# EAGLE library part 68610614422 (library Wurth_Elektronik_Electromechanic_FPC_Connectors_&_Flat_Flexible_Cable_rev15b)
WR-FPC 1.00mm SMT ZIF Horizontal Bottom Contact, 6 Pins=>Code : Con_FPC_ZIF_1.00_68610614422 Details see: http://katalog.we-online.de/en/em/686_1xx_144_22 Created 2014-07-09, Karrer Zheng 2014 (C) Würth Elektronik

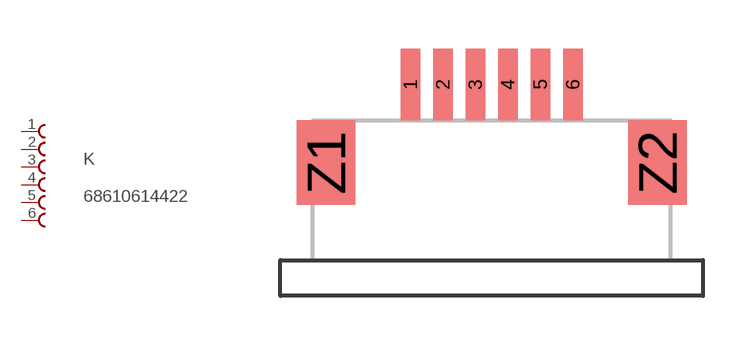
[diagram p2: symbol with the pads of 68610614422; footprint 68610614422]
Designator prefix K

## 68610614422  [68610614422]
1  1  pas
2  2  pas
3  3  pas
4  4  pas
5  5  pas
6  6  pas

## Footprint 68610614422 (pad centres in mm)
WR-FPC 1.00mm SMT ZIF Horizontal Bottom Contact, 6 Pins
smd 0.6 x 2.2: 1 -2.5,1.1; 2 -1.5,1.1; 3 -0.5,1.1; 4 0.5,1.1; 5 1.5,1.1; 6 2.5,1.1
smd 1.8 x 2.6: Z1 -5.1,-1.3; Z2 5.1,-1.3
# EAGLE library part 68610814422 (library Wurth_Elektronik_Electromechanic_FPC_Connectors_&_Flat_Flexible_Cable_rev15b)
WR-FPC 1.00mm SMT ZIF Horizontal Bottom Contact, 8 Pins=>Code : Con_FPC_ZIF_1.00_68610814422 Details see: http://katalog.we-online.de/en/em/686_1xx_144_22 Created 2014-07-09, Karrer Zheng 2014 (C) Würth Elektronik

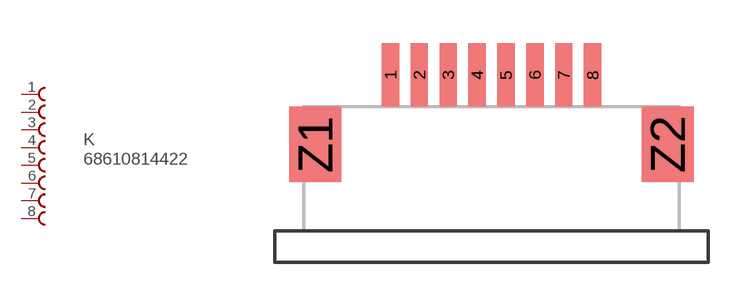
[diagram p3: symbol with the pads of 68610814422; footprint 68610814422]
Designator prefix K

## 68610814422  [68610814422]
1  1  pas
2  2  pas
3  3  pas
4  4  pas
5  5  pas
6  6  pas
7  7  pas
8  8  pas

## Footprint 68610814422 (pad centres in mm)
WR-FPC 1.00mm SMT ZIF Horizontal Bottom Contact, 8 Pins
smd 0.6 x 2.2: 1 -4.5,1.1; 2 -3.5,1.1; 3 -2.5,1.1; 4 -1.5,1.1; 5 -0.5,1.1; 6 0.5,1.1; 7 1.5,1.1; 8 2.5,1.1
smd 1.8 x 2.6: Z1 -7.1,-1.3; Z2 5.1,-1.3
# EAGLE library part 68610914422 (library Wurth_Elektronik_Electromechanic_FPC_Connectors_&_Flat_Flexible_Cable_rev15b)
WR-FPC 1.00mm SMT ZIF Horizontal Bottom Contact, 9 Pins=>Code : Con_FPC_ZIF_1.00_68610914422 Details see: http://katalog.we-online.de/en/em/686_1xx_144_22 Created 2014-07-09, Karrer Zheng 2014 (C) Würth Elektronik

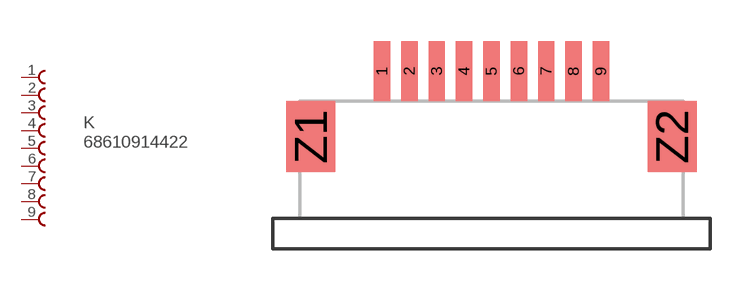
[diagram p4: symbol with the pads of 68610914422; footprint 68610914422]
Designator prefix K

## 68610914422  [68610914422]
1  1  pas
2  2  pas
3  3  pas
4  4  pas
5  5  pas
6  6  pas
7  7  pas
8  8  pas
9  9  pas

## Footprint 68610914422 (pad centres in mm)
WR-FPC 1.00mm SMT ZIF Horizontal Bottom Contact, 9 Pins
smd 0.6 x 2.2: 1 -7.04,1.1; 2 -6.04,1.1; 3 -5.04,1.1; 4 -4.04,1.1; 5 -3.04,1.1; 6 -2.04,1.1; 7 -1.04,1.1; 8 -0.04,1.1; 9 0.96,1.1
smd 1.8 x 2.6: Z1 -9.64,-1.3; Z2 3.56,-1.3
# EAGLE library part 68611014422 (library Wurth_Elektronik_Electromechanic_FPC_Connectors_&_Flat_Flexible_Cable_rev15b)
WR-FPC 1.00mm SMT ZIF Horizontal Bottom Contact, 10 Pins=>Code : Con_FPC_ZIF_1.00_68611014422 Details see: http://katalog.we-online.de/en/em/686_1xx_144_22 Created 2014-07-09, Karrer Zheng 2014 (C) Würth Elektronik

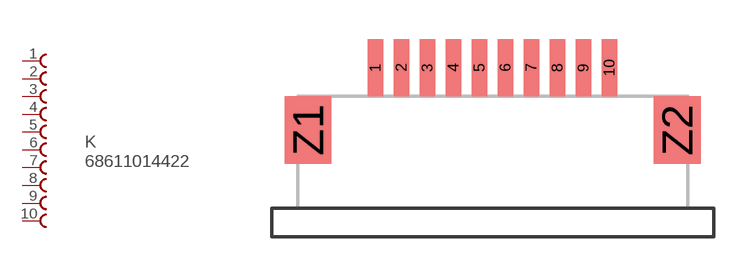
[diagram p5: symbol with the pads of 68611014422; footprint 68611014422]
Designator prefix K

## 68611014422  [68611014422]
1  1  pas
2  2  pas
3  3  pas
4  4  pas
5  5  pas
6  6  pas
7  7  pas
8  8  pas
9  9  pas
10  10  pas

## Footprint 68611014422 (pad centres in mm)
WR-FPC 1.00mm SMT ZIF Horizontal Bottom Contact, 10 Pins
smd 0.6 x 2.2: 1 -7.5,1.1; 2 -6.5,1.1; 3 -5.5,1.1; 4 -4.5,1.1; 5 -3.5,1.1; 6 -2.5,1.1; 7 -1.5,1.1; 8 -0.5,1.1; 9 0.5,1.1; 10 1.5,1.1
smd 1.8 x 2.6: Z1 -10.1,-1.3; Z2 4.1,-1.3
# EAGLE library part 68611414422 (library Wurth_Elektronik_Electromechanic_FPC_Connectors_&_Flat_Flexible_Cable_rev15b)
WR-FPC 1.00mm SMT ZIF Horizontal Bottom Contact, 14 Pins=>Code : Con_FPC_ZIF_1.00_68611414422 Details see: http://katalog.we-online.de/en/em/686_1xx_144_22 Created 2014-07-09, Karrer Zheng 2014 (C) Würth Elektronik

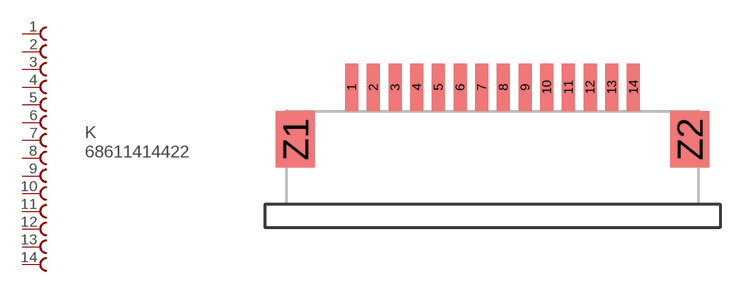
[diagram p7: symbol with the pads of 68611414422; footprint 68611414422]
Designator prefix K

## 68611414422  [68611414422]
1  1  pas
2  2  pas
3  3  pas
4  4  pas
5  5  pas
6  6  pas
7  7  pas
8  8  pas
9  9  pas
10  10  pas
11  11  pas
12  12  pas
13  13  pas
14  14  pas

## Footprint 68611414422 (pad centres in mm)
WR-FPC 1.00mm SMT ZIF Horizontal Bottom Contact, 14 Pins
smd 0.6 x 2.2: 1 -9.77,1.1; 2 -8.77,1.1; 3 -7.77,1.1; 4 -6.77,1.1; 5 -5.77,1.1; 6 -4.77,1.1; 7 -3.77,1.1; 8 -2.77,1.1; 9 -1.77,1.1; 10 -0.77,1.1; 11 0.23,1.1; 12 1.23,1.1; 13 2.23,1.1; 14 3.23,1.1
smd 1.8 x 2.6: Z1 -12.37,-1.3; Z2 5.83,-1.3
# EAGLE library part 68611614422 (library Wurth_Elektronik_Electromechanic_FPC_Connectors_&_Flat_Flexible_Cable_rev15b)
WR-FPC 1.00mm SMT ZIF Horizontal Bottom Contact, 16 Pins=>Code : Con_FPC_ZIF_1.00_68611614422 Details see: http://katalog.we-online.de/en/em/686_1xx_144_22 Created 2014-07-09, Karrer Zheng 2014 (C) Würth Elektronik

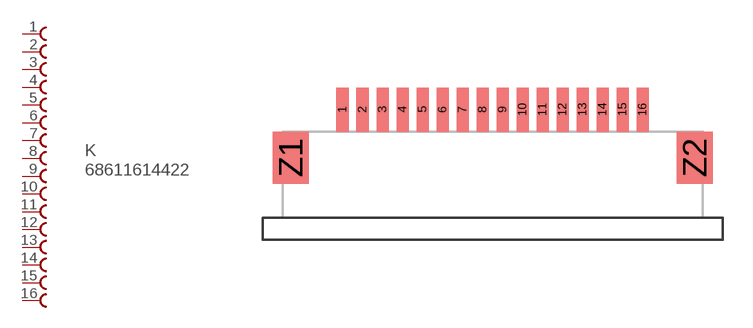
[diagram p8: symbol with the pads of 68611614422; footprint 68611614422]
Designator prefix K

## 68611614422  [68611614422]
1  1  pas
2  2  pas
3  3  pas
4  4  pas
5  5  pas
6  6  pas
7  7  pas
8  8  pas
9  9  pas
10  10  pas
11  11  pas
12  12  pas
13  13  pas
14  14  pas
15  15  pas
16  16  pas

## Footprint 68611614422 (pad centres in mm)
WR-FPC 1.00mm SMT ZIF Horizontal Bottom Contact, 16 Pins
smd 0.6 x 2.2: 1 -11.96,1.1; 2 -10.96,1.1; 3 -9.96,1.1; 4 -8.96,1.1; 5 -7.96,1.1; 6 -6.96,1.1; 7 -5.96,1.1; 8 -4.96,1.1; 9 -3.96,1.1; 10 -2.96,1.1; 11 -1.96,1.1; 12 -0.96,1.1; 13 0.04,1.1; 14 1.04,1.1; 15 2.04,1.1; 16 3.04,1.1
smd 1.8 x 2.6: Z1 -14.56,-1.3; Z2 5.64,-1.3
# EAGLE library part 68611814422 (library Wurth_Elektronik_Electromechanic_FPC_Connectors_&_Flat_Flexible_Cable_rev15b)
WR-FPC 1.00mm SMT ZIF Horizontal Bottom Contact, 18 Pins=>Code : Con_FPC_ZIF_1.00_68611814422 Details see: http://katalog.we-online.de/en/em/686_1xx_144_22 Created 2014-07-09, Karrer Zheng 2014 (C) Würth Elektronik

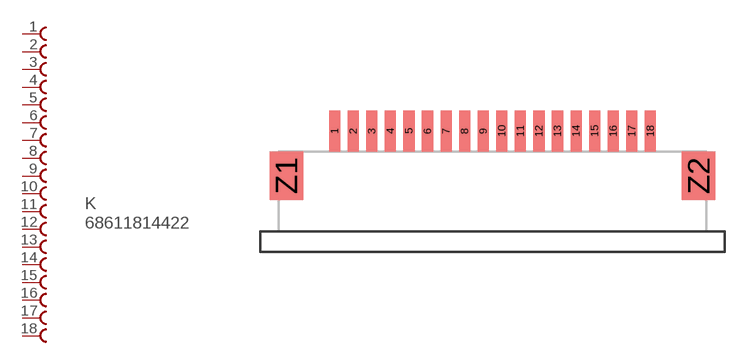
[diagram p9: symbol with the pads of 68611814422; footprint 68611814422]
Designator prefix K

## 68611814422  [68611814422]
1  1  pas
2  2  pas
3  3  pas
4  4  pas
5  5  pas
6  6  pas
7  7  pas
8  8  pas
9  9  pas
10  10  pas
11  11  pas
12  12  pas
13  13  pas
14  14  pas
15  15  pas
16  16  pas
17  17  pas
18  18  pas

## Footprint 68611814422 (pad centres in mm)
WR-FPC 1.00mm SMT ZIF Horizontal Bottom Contact, 18 Pins
smd 0.6 x 2.2: 1 -14.5,1.1; 2 -13.5,1.1; 3 -12.5,1.1; 4 -11.5,1.1; 5 -10.5,1.1; 6 -9.5,1.1; 7 -8.5,1.1; 8 -7.5,1.1; 9 -6.5,1.1; 10 -5.5,1.1; 11 -4.5,1.1; 12 -3.5,1.1; 13 -2.5,1.1; 14 -1.5,1.1; 15 -0.5,1.1; 16 0.5,1.1; 17 1.5,1.1; 18 2.5,1.1
smd 1.8 x 2.6: Z1 -17.1,-1.3; Z2 5.1,-1.3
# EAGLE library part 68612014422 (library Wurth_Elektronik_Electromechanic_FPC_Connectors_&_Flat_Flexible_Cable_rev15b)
WR-FPC 1.00mm SMT ZIF Horizontal Bottom Contact, 20 Pins=>Code : Con_FPC_ZIF_1.00_68612014422 Details see: http://katalog.we-online.de/en/em/686_1xx_144_22 Created 2014-07-09, Karrer Zheng 2014 (C) Würth Elektronik

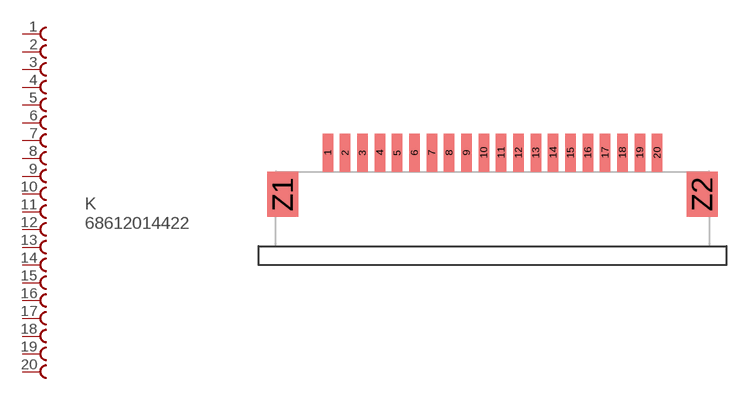
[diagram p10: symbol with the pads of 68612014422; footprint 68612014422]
Designator prefix K

## 68612014422  [68612014422]
1  1  pas
2  2  pas
3  3  pas
4  4  pas
5  5  pas
6  6  pas
7  7  pas
8  8  pas
9  9  pas
10  10  pas
11  11  pas
12  12  pas
13  13  pas
14  14  pas
15  15  pas
16  16  pas
17  17  pas
18  18  pas
19  19  pas
20  20  pas

## Footprint 68612014422 (pad centres in mm)
WR-FPC 1.00mm SMT ZIF Horizontal Bottom Contact, 20 Pins
smd 0.6 x 2.2: 1 -15.77,1.1; 2 -14.77,1.1; 3 -13.77,1.1; 4 -12.77,1.1; 5 -11.77,1.1; 6 -10.77,1.1; 7 -9.77,1.1; 8 -8.77,1.1; 9 -7.77,1.1; 10 -6.77,1.1; 11 -5.77,1.1; 12 -4.77,1.1; 13 -3.77,1.1; 14 -2.77,1.1; 15 -1.77,1.1; 16 -0.77,1.1; 17 0.23,1.1; 18 1.23,1.1; 19 2.23,1.1; 20 3.23,1.1
smd 1.8 x 2.6: Z1 -18.37,-1.3; Z2 5.83,-1.3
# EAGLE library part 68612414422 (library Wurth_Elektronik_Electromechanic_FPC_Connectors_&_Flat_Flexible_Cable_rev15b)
WR-FPC 1.00mm SMT ZIF Horizontal Bottom Contact, 24 Pins=>Code : Con_FPC_ZIF_1.00_68612414422 Details see: http://katalog.we-online.de/en/em/686_1xx_144_22 Created 2014-07-09, Karrer Zheng 2014 (C) Würth Elektronik

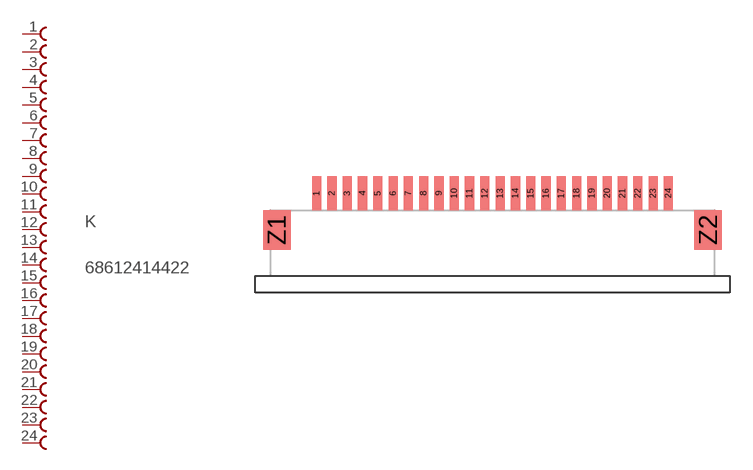
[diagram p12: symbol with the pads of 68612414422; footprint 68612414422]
Designator prefix K

## 68612414422  [68612414422]
1  1  pas
2  2  pas
3  3  pas
4  4  pas
5  5  pas
6  6  pas
7  7  pas
8  8  pas
9  9  pas
10  10  pas
11  11  pas
12  12  pas
13  13  pas
14  14  pas
15  15  pas
16  16  pas
17  17  pas
18  18  pas
19  19  pas
20  20  pas
21  21  pas
22  22  pas
23  23  pas
24  24  pas

## Footprint 68612414422 (pad centres in mm)
WR-FPC 1.00mm SMT ZIF Horizontal Bottom Contact, 24 Pins
smd 0.6 x 2.2: 1 -17.04,1.1; 2 -16.04,1.1; 3 -15.04,1.1; 4 -14.04,1.1; 5 -13.04,1.1; 6 -12.04,1.1; 7 -11.04,1.1; 8 -10.04,1.1; 9 -9.04,1.1; 10 -8.04,1.1; 11 -7.04,1.1; 12 -6.04,1.1; 13 -5.04,1.1; 14 -4.04,1.1; 15 -3.04,1.1; 16 -2.04,1.1; 17 -1.04,1.1; 18 -0.04,1.1; 19 0.96,1.1; 20 1.96,1.1; 21 2.96,1.1; 22 3.96,1.1; 23 4.96,1.1; 24 5.96,1.1
smd 1.8 x 2.6: Z1 -19.64,-1.3; Z2 8.56,-1.3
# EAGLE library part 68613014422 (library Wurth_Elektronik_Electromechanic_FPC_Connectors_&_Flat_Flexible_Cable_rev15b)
WR-FPC 1.00mm SMT ZIF Horizontal Bottom Contact, 30 Pins=>Code : Con_FPC_ZIF_1.00_68613014422 Details see: http://katalog.we-online.de/en/em/686_1xx_144_22 Created 2014-07-09, Karrer Zheng 2014 (C) Würth Elektronik

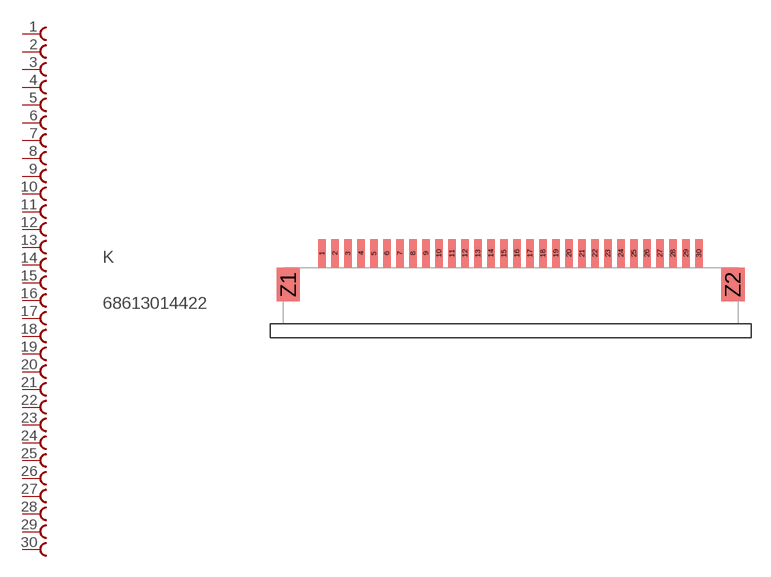
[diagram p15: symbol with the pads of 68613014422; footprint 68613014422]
Designator prefix K

## 68613014422  [68613014422]
1  1  pas
2  2  pas
3  3  pas
4  4  pas
5  5  pas
6  6  pas
7  7  pas
8  8  pas
9  9  pas
10  10  pas
11  11  pas
12  12  pas
13  13  pas
14  14  pas
15  15  pas
16  16  pas
17  17  pas
18  18  pas
19  19  pas
20  20  pas
21  21  pas
22  22  pas
23  23  pas
24  24  pas
25  25  pas
26  26  pas
27  27  pas
28  28  pas
29  29  pas
30  30  pas

## Footprint 68613014422 (pad centres in mm)
WR-FPC 1.00mm SMT ZIF Horizontal Bottom Contact, 30 Pins
smd 0.6 x 2.2: 1 -22.93,1.1; 2 -21.93,1.1; 3 -20.93,1.1; 4 -19.93,1.1; 5 -18.93,1.1; 6 -17.93,1.1; 7 -16.93,1.1; 8 -15.93,1.1; 9 -14.93,1.1; 10 -13.93,1.1; 11 -12.93,1.1; 12 -11.93,1.1; 13 -10.93,1.1; 14 -9.93,1.1; 15 -8.93,1.1; 16 -7.93,1.1; 17 -6.93,1.1; 18 -5.93,1.1; 19 -4.93,1.1; 20 -3.93,1.1; 21 -2.93,1.1; 22 -1.93,1.1; 23 -0.93,1.1; 24 0.07,1.1; 25 1.07,1.1; 26 2.07,1.1; 27 3.07,1.1; 28 4.07,1.1; 29 5.07,1.1; 30 6.07,1.1
smd 1.8 x 2.6: Z1 -25.53,-1.3; Z2 8.67,-1.3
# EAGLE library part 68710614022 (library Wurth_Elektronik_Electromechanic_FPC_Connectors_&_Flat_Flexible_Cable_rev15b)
WR-FPC 0.5mm SMT ZIF Horizontal Top Contact, 6 Pins=>Code : Con_FPC_ZIF_0.50_68710614022 Details see: http://katalog.we-online.de/en/em/687_1xx_140_22 Created 2014-07-09, Karrer Zheng 2014 (C) Würth Elektronik

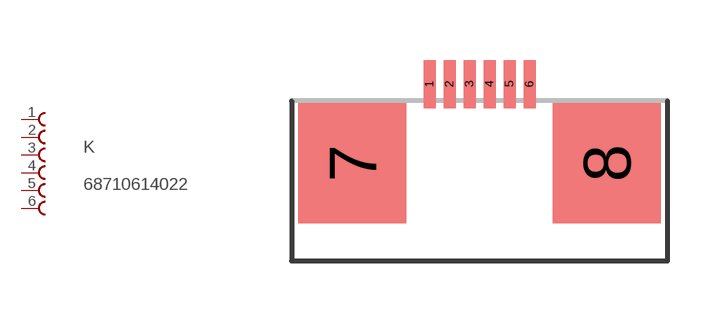
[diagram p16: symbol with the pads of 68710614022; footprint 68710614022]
Designator prefix K

## 68710614022  [68710614022]
1  1  pas
2  2  pas
3  3  pas
4  4  pas
5  5  pas
6  6  pas

## Footprint 68710614022 (pad centres in mm)
WR-FPC 0.5mm SMT ZIF Horizontal Top Contact, 6 Pins
smd 0.3 x 1.2: 1 0.25,0.54; 2 0.75,0.54; 3 1.25,0.54; 4 1.75,0.54; 5 2.25,0.54; 6 2.75,0.54
smd 2.7 x 3: 7 -1.68,-1.44; 8 4.68,-1.44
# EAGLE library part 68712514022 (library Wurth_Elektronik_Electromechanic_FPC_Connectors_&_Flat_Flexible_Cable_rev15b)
WR-FPC 0.5mm SMT ZIF Horizontal Top Contact, 25 Pins=>Code : Con_FPC_ZIF_0.50_68712514022 Details see: http://katalog.we-online.de/en/em/687_1xx_140_22 Created 2014-07-09, Karrer Zheng 2014 (C) Würth Elektronik

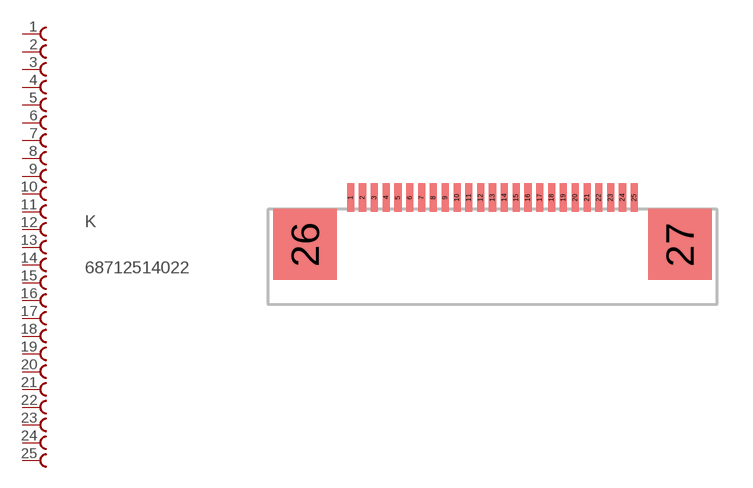
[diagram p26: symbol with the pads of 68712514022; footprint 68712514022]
Designator prefix K

## 68712514022  [68712514022]
1  1  pas
2  2  pas
3  3  pas
4  4  pas
5  5  pas
6  6  pas
7  7  pas
8  8  pas
9  9  pas
10  10  pas
11  11  pas
12  12  pas
13  13  pas
14  14  pas
15  15  pas
16  16  pas
17  17  pas
18  18  pas
19  19  pas
20  20  pas
21  21  pas
22  22  pas
23  23  pas
24  24  pas
25  25  pas

## Footprint 68712514022 (pad centres in mm)
WR-FPC 0.5mm SMT ZIF Horizontal Top Contact, 25 Pins
smd 0.3 x 1.2: 1 -5.25,0.6; 2 -4.75,0.6; 3 -4.25,0.6; 4 -3.75,0.6; 5 -3.25,0.6; 6 -2.75,0.6; 7 -2.25,0.6; 8 -1.75,0.6; 9 -1.25,0.6; 10 -0.75,0.6; 11 -0.25,0.6; 12 0.25,0.6; 13 0.75,0.6; 14 1.25,0.6; 15 1.75,0.6; 16 2.25,0.6; 17 2.75,0.6; 18 3.25,0.6; 19 3.75,0.6; 20 4.25,0.6; 21 4.75,0.6; 22 5.25,0.6; 23 5.75,0.6; 24 6.25,0.6; 25 6.75,0.6
smd 2.7 x 3: 26 -7.18,-1.38; 27 8.68,-1.38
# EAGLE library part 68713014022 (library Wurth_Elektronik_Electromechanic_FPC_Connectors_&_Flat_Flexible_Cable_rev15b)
WR-FPC 0.5mm SMT ZIF Horizontal Top Contact, 30 Pins=>Code : Con_FPC_ZIF_0.50_68713014022 Details see: http://katalog.we-online.de/en/em/687_1xx_140_22 Created 2014-07-09, Karrer Zheng 2014 (C) Würth Elektronik

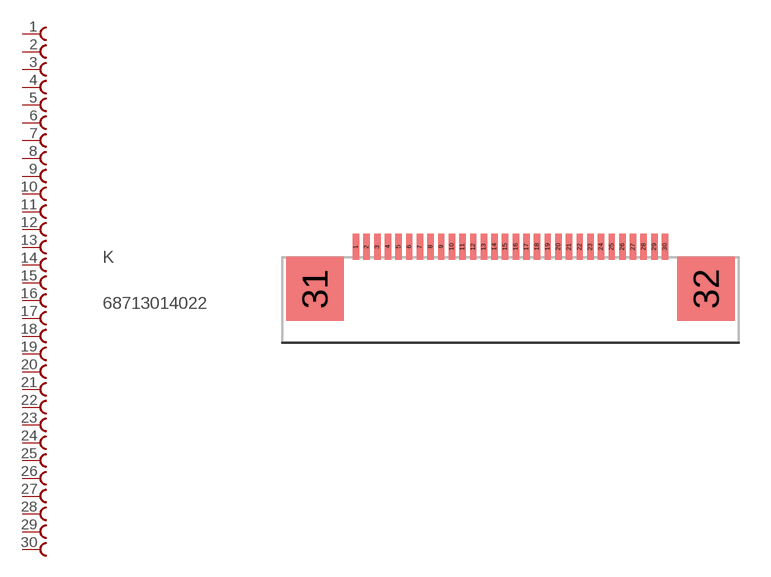
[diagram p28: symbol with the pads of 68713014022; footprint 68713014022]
Designator prefix K

## 68713014022  [68713014022]
1  1  pas
2  2  pas
3  3  pas
4  4  pas
5  5  pas
6  6  pas
7  7  pas
8  8  pas
9  9  pas
10  10  pas
11  11  pas
12  12  pas
13  13  pas
14  14  pas
15  15  pas
16  16  pas
17  17  pas
18  18  pas
19  19  pas
20  20  pas
21  21  pas
22  22  pas
23  23  pas
24  24  pas
25  25  pas
26  26  pas
27  27  pas
28  28  pas
29  29  pas
30  30  pas

## Footprint 68713014022 (pad centres in mm)
WR-FPC 0.5mm SMT ZIF Horizontal Top Contact, 30 Pins
smd 0.3 x 1.2: 1 -7.25,0.62; 2 -6.75,0.62; 3 -6.25,0.62; 4 -5.75,0.62; 5 -5.25,0.62; 6 -4.75,0.62; 7 -4.25,0.62; 8 -3.75,0.62; 9 -3.25,0.62; 10 -2.75,0.62; 11 -2.25,0.62; 12 -1.75,0.62; 13 -1.25,0.62; 14 -0.75,0.62; 15 -0.25,0.62; 16 0.25,0.62; 17 0.75,0.62; 18 1.25,0.62; 19 1.75,0.62; 20 2.25,0.62; 21 2.75,0.62; 22 3.25,0.62; 23 3.75,0.62; 24 4.25,0.62; 25 4.75,0.62; 26 5.25,0.62; 27 5.75,0.62; 28 6.25,0.62; 29 6.75,0.62; 30 7.25,0.62
smd 2.7 x 3: 31 -9.18,-1.36; 32 9.18,-1.36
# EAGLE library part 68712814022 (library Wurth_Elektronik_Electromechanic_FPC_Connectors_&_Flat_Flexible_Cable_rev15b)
WR-FPC 0.5mm SMT ZIF Horizontal Top Contact, 28 Pins=>Code : Con_FPC_ZIF_0.50_68712814022 Details see: http://katalog.we-online.de/en/em/687_1xx_140_22 Created 2014-07-09, Karrer Zheng 2014 (C) Würth Elektronik

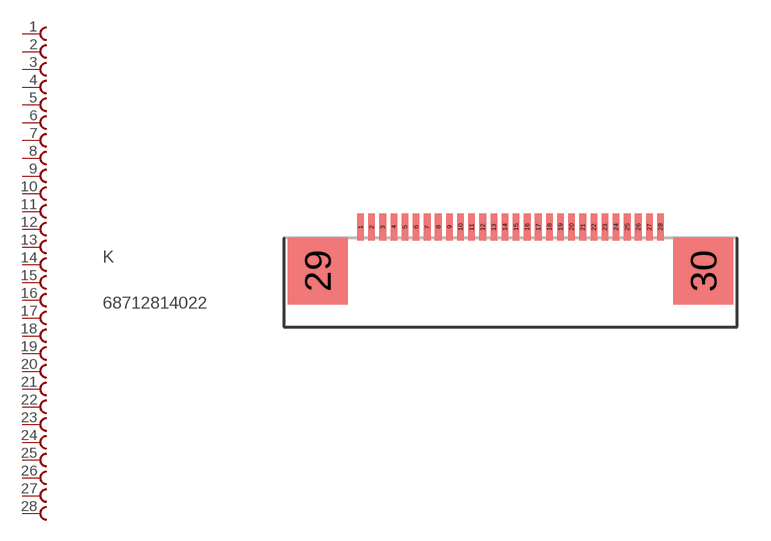
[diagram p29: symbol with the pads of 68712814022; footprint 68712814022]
Designator prefix K

## 68712814022  [68712814022]
1  1  pas
2  2  pas
3  3  pas
4  4  pas
5  5  pas
6  6  pas
7  7  pas
8  8  pas
9  9  pas
10  10  pas
11  11  pas
12  12  pas
13  13  pas
14  14  pas
15  15  pas
16  16  pas
17  17  pas
18  18  pas
19  19  pas
20  20  pas
21  21  pas
22  22  pas
23  23  pas
24  24  pas
25  25  pas
26  26  pas
27  27  pas
28  28  pas

## Footprint 68712814022 (pad centres in mm)
WR-FPC 0.5mm SMT ZIF Horizontal Top Contact, 28 Pins
smd 0.3 x 1.2: 1 -6.75,0.6; 2 -6.25,0.6; 3 -5.75,0.6; 4 -5.25,0.6; 5 -4.75,0.6; 6 -4.25,0.6; 7 -3.75,0.6; 8 -3.25,0.6; 9 -2.75,0.6; 10 -2.25,0.6; 11 -1.75,0.6; 12 -1.25,0.6; 13 -0.75,0.6; 14 -0.25,0.6; 15 0.25,0.6; 16 0.75,0.6; 17 1.25,0.6; 18 1.75,0.6; 19 2.25,0.6; 20 2.75,0.6; 21 3.25,0.6; 22 3.75,0.6; 23 4.25,0.6; 24 4.75,0.6; 25 5.25,0.6; 26 5.75,0.6; 27 6.25,0.6; 28 6.75,0.6
smd 2.7 x 3: 29 -8.68,-1.38; 30 8.68,-1.38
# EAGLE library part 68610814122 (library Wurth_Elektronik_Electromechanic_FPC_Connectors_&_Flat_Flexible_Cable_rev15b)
WR-FPC 1.00mm SMT ZIF Horizontal Top Contact, 8 Pins=>Code : Con_FPC_ZIF_1.00_68610814122 Details see: http://katalog.we-online.de/en/em/686_1xx_141_22 Created 2014-07-09, Karrer Zheng 2014 (C) Würth Elektronik

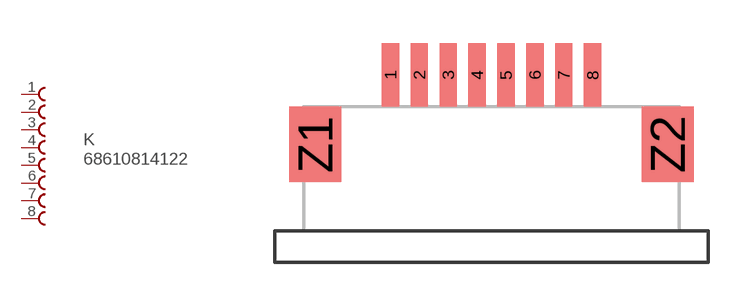
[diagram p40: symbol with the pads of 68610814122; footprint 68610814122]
Designator prefix K

## 68610814122  [68610814122]
1  1  pas
2  2  pas
3  3  pas
4  4  pas
5  5  pas
6  6  pas
7  7  pas
8  8  pas

## Footprint 68610814122 (pad centres in mm)
WR-FPC 1.00mm SMT ZIF Horizontal Top Contact, 8 Pins
smd 0.6 x 2.2: 1 -3.23,1.1; 2 -2.23,1.1; 3 -1.23,1.1; 4 -0.23,1.1; 5 0.77,1.1; 6 1.77,1.1; 7 2.77,1.1; 8 3.77,1.1
smd 1.8 x 2.6: Z1 -5.83,-1.3; Z2 6.37,-1.3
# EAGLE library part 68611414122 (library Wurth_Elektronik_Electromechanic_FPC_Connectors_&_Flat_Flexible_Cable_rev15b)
WR-FPC 1.00mm SMT ZIF Horizontal Top Contact, 14 Pins=>Code : Con_FPC_ZIF_1.00_68611414122 Details see: http://katalog.we-online.de/en/em/686_1xx_141_22 Created 2014-07-09, Karrer Zheng 2014 (C) Würth Elektronik

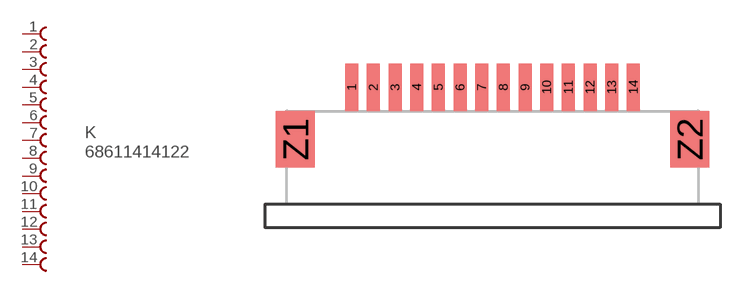
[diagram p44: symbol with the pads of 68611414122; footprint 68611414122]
Designator prefix K

## 68611414122  [68611414122]
1  1  pas
2  2  pas
3  3  pas
4  4  pas
5  5  pas
6  6  pas
7  7  pas
8  8  pas
9  9  pas
10  10  pas
11  11  pas
12  12  pas
13  13  pas
14  14  pas

## Footprint 68611414122 (pad centres in mm)
WR-FPC 1.00mm SMT ZIF Horizontal Top Contact, 14 Pins
smd 0.6 x 2.2: 1 -8.5,1.1; 2 -7.5,1.1; 3 -6.5,1.1; 4 -5.5,1.1; 5 -4.5,1.1; 6 -3.5,1.1; 7 -2.5,1.1; 8 -1.5,1.1; 9 -0.5,1.1; 10 0.5,1.1; 11 1.5,1.1; 12 2.5,1.1; 13 3.5,1.1; 14 4.5,1.1
smd 1.8 x 2.6: Z1 -11.1,-1.3; Z2 7.1,-1.3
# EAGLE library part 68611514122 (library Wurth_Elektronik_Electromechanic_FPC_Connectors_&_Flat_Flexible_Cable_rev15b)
WR-FPC 1.00mm SMT ZIF Horizontal Top Contact, 15 Pins=>Code : Con_FPC_ZIF_1.00_68611514122 Details see: http://katalog.we-online.de/en/em/686_1xx_141_22 Created 2014-07-09, Karrer Zheng 2014 (C) Würth Elektronik

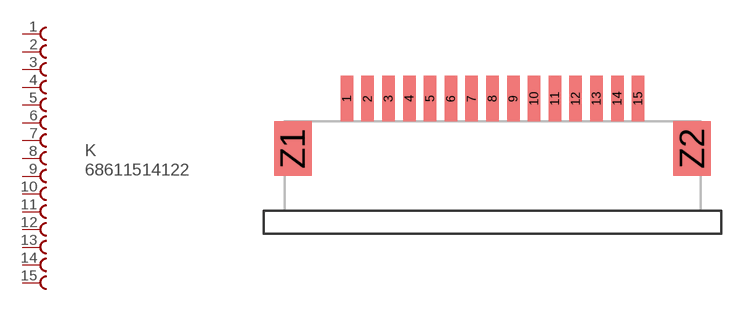
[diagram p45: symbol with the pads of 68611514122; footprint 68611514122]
Designator prefix K

## 68611514122  [68611514122]
1  1  pas
2  2  pas
3  3  pas
4  4  pas
5  5  pas
6  6  pas
7  7  pas
8  8  pas
9  9  pas
10  10  pas
11  11  pas
12  12  pas
13  13  pas
14  14  pas
15  15  pas

## Footprint 68611514122 (pad centres in mm)
WR-FPC 1.00mm SMT ZIF Horizontal Top Contact, 15 Pins
smd 0.6 x 2.2: 1 -10.54,1.1; 2 -9.54,1.1; 3 -8.54,1.1; 4 -7.54,1.1; 5 -6.54,1.1; 6 -5.54,1.1; 7 -4.54,1.1; 8 -3.54,1.1; 9 -2.54,1.1; 10 -1.54,1.1; 11 -0.54,1.1; 12 0.46,1.1; 13 1.46,1.1; 14 2.46,1.1; 15 3.46,1.1
smd 1.8 x 2.6: Z1 -13.14,-1.3; Z2 6.06,-1.3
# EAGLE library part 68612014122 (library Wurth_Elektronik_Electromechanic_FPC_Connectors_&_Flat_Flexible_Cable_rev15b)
WR-FPC 1.00mm SMT ZIF Horizontal Top Contact, 20 Pins=>Code : Con_FPC_ZIF_1.00_68612014122 Details see: http://katalog.we-online.de/en/em/686_1xx_141_22 Created 2014-07-09, Karrer Zheng 2014 (C) Würth Elektronik

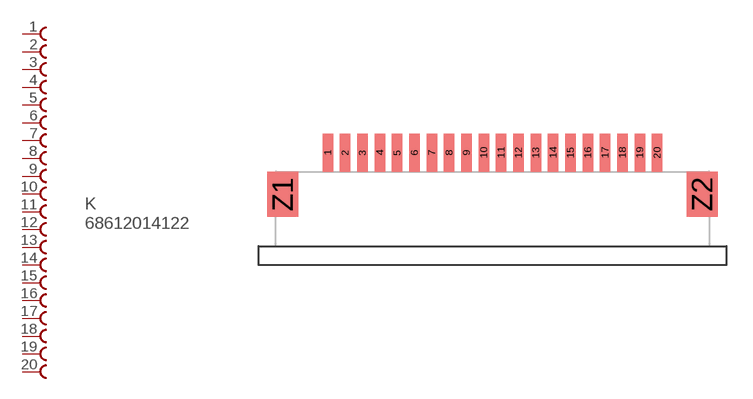
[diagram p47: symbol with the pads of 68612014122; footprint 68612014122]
Designator prefix K

## 68612014122  [68612014122]
1  1  pas
2  2  pas
3  3  pas
4  4  pas
5  5  pas
6  6  pas
7  7  pas
8  8  pas
9  9  pas
10  10  pas
11  11  pas
12  12  pas
13  13  pas
14  14  pas
15  15  pas
16  16  pas
17  17  pas
18  18  pas
19  19  pas
20  20  pas

## Footprint 68612014122 (pad centres in mm)
WR-FPC 1.00mm SMT ZIF Horizontal Top Contact, 20 Pins
smd 0.6 x 2.2: 1 -9.42,1.1; 2 -8.42,1.1; 3 -7.42,1.1; 4 -6.42,1.1; 5 -5.42,1.1; 6 -4.42,1.1; 7 -3.42,1.1; 8 -2.42,1.1; 9 -1.42,1.1; 10 -0.42,1.1; 11 0.58,1.1; 12 1.58,1.1; 13 2.58,1.1; 14 3.58,1.1; 15 4.58,1.1; 16 5.58,1.1; 17 6.58,1.1; 18 7.58,1.1; 19 8.58,1.1; 20 9.58,1.1
smd 1.8 x 2.6: Z1 -12.02,-1.3; Z2 12.18,-1.3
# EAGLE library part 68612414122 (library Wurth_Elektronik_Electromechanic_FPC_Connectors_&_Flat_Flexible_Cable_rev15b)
WR-FPC 1.00mm SMT ZIF Horizontal Top Contact, 24 Pins=>Code : Con_FPC_ZIF_1.00_68612414122 Details see: http://katalog.we-online.de/en/em/686_1xx_141_22 Created 2014-07-09, Karrer Zheng 2014 (C) Würth Elektronik

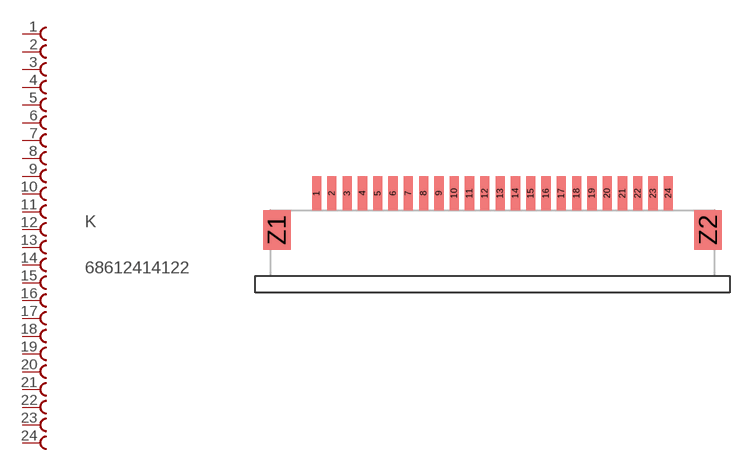
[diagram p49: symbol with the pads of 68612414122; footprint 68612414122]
Designator prefix K

## 68612414122  [68612414122]
1  1  pas
2  2  pas
3  3  pas
4  4  pas
5  5  pas
6  6  pas
7  7  pas
8  8  pas
9  9  pas
10  10  pas
11  11  pas
12  12  pas
13  13  pas
14  14  pas
15  15  pas
16  16  pas
17  17  pas
18  18  pas
19  19  pas
20  20  pas
21  21  pas
22  22  pas
23  23  pas
24  24  pas

## Footprint 68612414122 (pad centres in mm)
WR-FPC 1.00mm SMT ZIF Horizontal Top Contact, 24 Pins
smd 0.6 x 2.2: 1 -10.69,1.1; 2 -9.69,1.1; 3 -8.69,1.1; 4 -7.69,1.1; 5 -6.69,1.1; 6 -5.69,1.1; 7 -4.69,1.1; 8 -3.69,1.1; 9 -2.69,1.1; 10 -1.69,1.1; 11 -0.69,1.1; 12 0.31,1.1; 13 1.31,1.1; 14 2.31,1.1; 15 3.31,1.1; 16 4.31,1.1; 17 5.31,1.1; 18 6.31,1.1; 19 7.31,1.1; 20 8.31,1.1; 21 9.31,1.1; 22 10.31,1.1; 23 11.31,1.1; 24 12.31,1.1
smd 1.8 x 2.6: Z1 -13.29,-1.3; Z2 14.91,-1.3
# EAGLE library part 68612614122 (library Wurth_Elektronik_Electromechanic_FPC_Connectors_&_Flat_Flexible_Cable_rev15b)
WR-FPC 1.00mm SMT ZIF Horizontal Top Contact, 26 Pins=>Code : Con_FPC_ZIF_1.00_68612614122 Details see: http://katalog.we-online.de/en/em/686_1xx_141_22 Created 2014-07-09, Karrer Zheng 2014 (C) Würth Elektronik

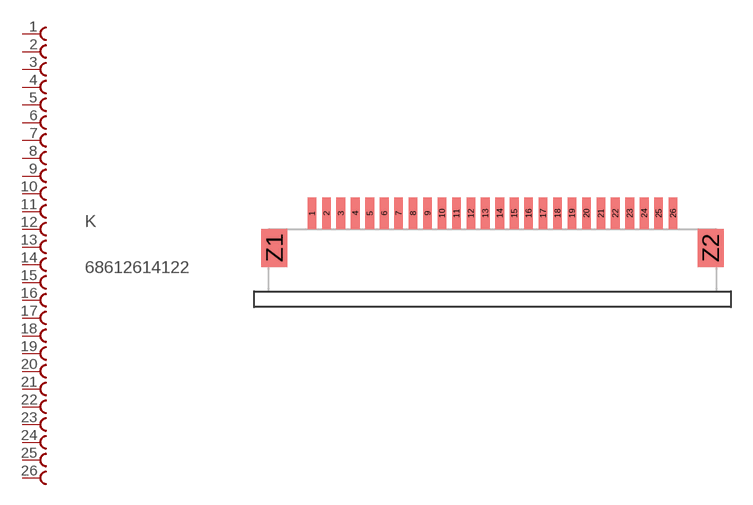
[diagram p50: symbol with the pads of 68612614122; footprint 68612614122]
Designator prefix K

## 68612614122  [68612614122]
1  1  pas
2  2  pas
3  3  pas
4  4  pas
5  5  pas
6  6  pas
7  7  pas
8  8  pas
9  9  pas
10  10  pas
11  11  pas
12  12  pas
13  13  pas
14  14  pas
15  15  pas
16  16  pas
17  17  pas
18  18  pas
19  19  pas
20  20  pas
21  21  pas
22  22  pas
23  23  pas
24  24  pas
25  25  pas
26  26  pas

## Footprint 68612614122 (pad centres in mm)
WR-FPC 1.00mm SMT ZIF Horizontal Top Contact, 26 Pins
smd 0.6 x 2.2: 1 -11.96,1.1; 2 -10.96,1.1; 3 -9.96,1.1; 4 -8.96,1.1; 5 -7.96,1.1; 6 -6.96,1.1; 7 -5.96,1.1; 8 -4.96,1.1; 9 -3.96,1.1; 10 -2.96,1.1; 11 -1.96,1.1; 12 -0.96,1.1; 13 0.04,1.1; 14 1.04,1.1; 15 2.04,1.1; 16 3.04,1.1; 17 4.04,1.1; 18 5.04,1.1; 19 6.04,1.1; 20 7.04,1.1; 21 8.04,1.1; 22 9.04,1.1; 23 10.04,1.1; 24 11.04,1.1; 25 12.04,1.1; 26 13.04,1.1
smd 1.8 x 2.6: Z1 -14.56,-1.3; Z2 15.64,-1.3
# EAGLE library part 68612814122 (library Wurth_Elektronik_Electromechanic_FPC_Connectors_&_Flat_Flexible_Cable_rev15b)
WR-FPC 1.00mm SMT ZIF Horizontal Top Contact, 28 Pins=>Code : Con_FPC_ZIF_1.00_68612814122 Details see: http://katalog.we-online.de/en/em/686_1xx_141_22 Created 2014-07-09, Karrer Zheng 2014 (C) Würth Elektronik

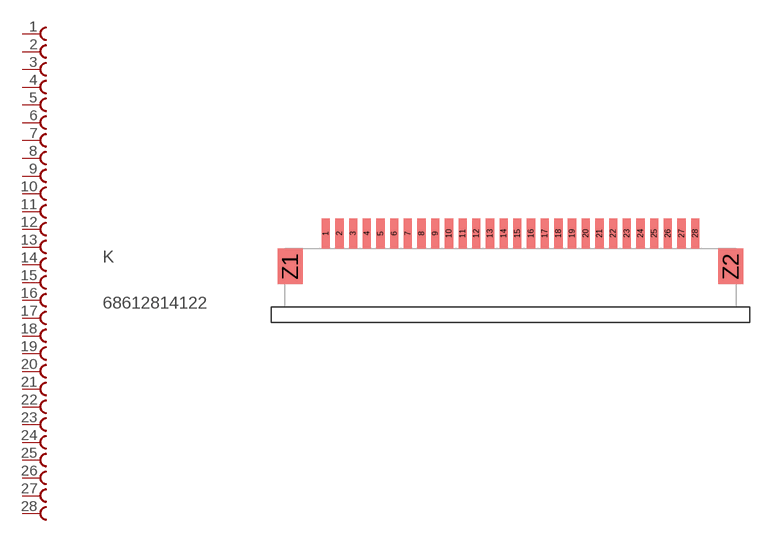
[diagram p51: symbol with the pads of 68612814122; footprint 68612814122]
Designator prefix K

## 68612814122  [68612814122]
1  1  pas
2  2  pas
3  3  pas
4  4  pas
5  5  pas
6  6  pas
7  7  pas
8  8  pas
9  9  pas
10  10  pas
11  11  pas
12  12  pas
13  13  pas
14  14  pas
15  15  pas
16  16  pas
17  17  pas
18  18  pas
19  19  pas
20  20  pas
21  21  pas
22  22  pas
23  23  pas
24  24  pas
25  25  pas
26  26  pas
27  27  pas
28  28  pas

## Footprint 68612814122 (pad centres in mm)
WR-FPC 1.00mm SMT ZIF Horizontal Top Contact, 28 Pins
smd 0.6 x 2.2: 1 -12.77,1.1; 2 -11.77,1.1; 3 -10.77,1.1; 4 -9.77,1.1; 5 -8.77,1.1; 6 -7.77,1.1; 7 -6.77,1.1; 8 -5.77,1.1; 9 -4.77,1.1; 10 -3.77,1.1; 11 -2.77,1.1; 12 -1.77,1.1; 13 -0.77,1.1; 14 0.23,1.1; 15 1.23,1.1; 16 2.23,1.1; 17 3.23,1.1; 18 4.23,1.1; 19 5.23,1.1; 20 6.23,1.1; 21 7.23,1.1; 22 8.23,1.1; 23 9.23,1.1; 24 10.23,1.1; 25 11.23,1.1; 26 12.23,1.1; 27 13.23,1.1; 28 14.23,1.1
smd 1.8 x 2.6: Z1 -15.37,-1.3; Z2 16.83,-1.3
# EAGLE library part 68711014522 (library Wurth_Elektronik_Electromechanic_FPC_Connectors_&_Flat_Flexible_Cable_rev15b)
WR-FPC 0.5mm SMT ZIF Horizontal Bottom Contact, 10 Pins=>Code : Con_FPC_ZIF_0.50_68711014522 Details see: http://katalog.we-online.de/en/em/687_1xx_145_22 Created 2014-07-09, Karrer Zheng 2014 (C) Würth Elektronik

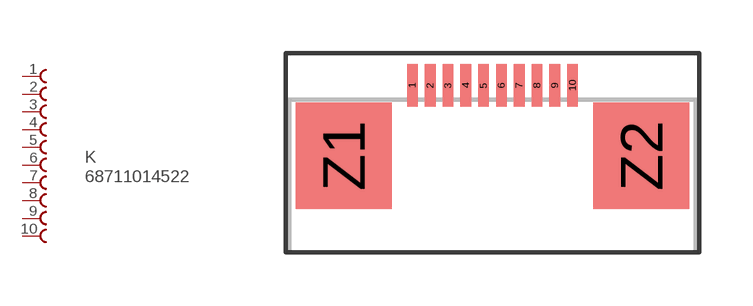
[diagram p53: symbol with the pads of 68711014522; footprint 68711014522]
Designator prefix K

## 68711014522  [68711014522]
1  1  pas
2  2  pas
3  3  pas
4  4  pas
5  5  pas
6  6  pas
7  7  pas
8  8  pas
9  9  pas
10  10  pas

## Footprint 68711014522 (pad centres in mm)
WR-FPC 0.5mm SMT ZIF Horizontal Bottom Contact, 10 Pins
smd 0.3 x 1.2: 1 -2.25,0.6; 2 -1.75,0.6; 3 -1.25,0.6; 4 -0.75,0.6; 5 -0.25,0.6; 6 0.25,0.6; 7 0.75,0.6; 8 1.25,0.6; 9 1.75,0.6; 10 2.25,0.6
smd 2.7 x 3: Z1 -4.18,-1.38; Z2 4.18,-1.38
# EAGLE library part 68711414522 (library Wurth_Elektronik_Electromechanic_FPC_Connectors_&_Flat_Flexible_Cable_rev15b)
WE-FPC 0.5mm SMT ZIF Horizontal Bottom Contact, 14 Pins=>Code : Con_FPC_ZIF_0.50_68711414522 Details see: http://katalog.we-online.de/en/em/687_1xx_145_22 Created 2014-07-09, Karrer Zheng 2014 (C) Würth Elektronik

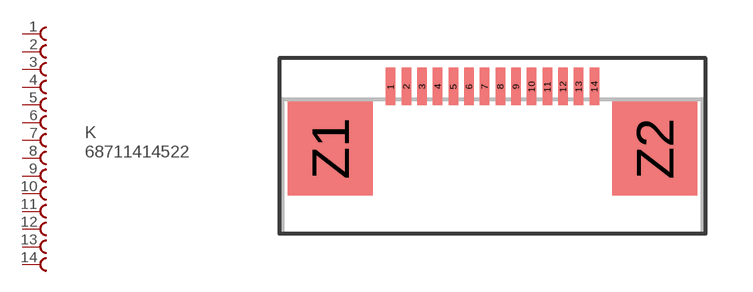
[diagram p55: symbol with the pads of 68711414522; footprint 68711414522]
Designator prefix K

## 68711414522  [68711414522]
1  1  pas
2  2  pas
3  3  pas
4  4  pas
5  5  pas
6  6  pas
7  7  pas
8  8  pas
9  9  pas
10  10  pas
11  11  pas
12  12  pas
13  13  pas
14  14  pas

## Footprint 68711414522 (pad centres in mm)
WE-FPC 0.5mm SMT ZIF Horizontal Bottom Contact, 14 Pins
smd 0.3 x 1.2: 1 -3.25,0.6; 2 -2.75,0.6; 3 -2.25,0.6; 4 -1.75,0.6; 5 -1.25,0.6; 6 -0.75,0.6; 7 -0.25,0.6; 8 0.25,0.6; 9 0.75,0.6; 10 1.25,0.6; 11 1.75,0.6; 12 2.25,0.6; 13 2.75,0.6; 14 3.25,0.6
smd 2.7 x 3: Z1 -5.18,-1.38; Z2 5.18,-1.38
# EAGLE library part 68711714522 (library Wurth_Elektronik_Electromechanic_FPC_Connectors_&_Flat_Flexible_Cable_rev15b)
WE-FPC 0.5mm SMT ZIF Horizontal Bottom Contact, 17 Pins=>Code : Con_FPC_ZIF_0.50_68711714522 Details see: http://katalog.we-online.de/en/em/687_1xx_145_22 Created 2014-07-09, Karrer Zheng 2014 (C) Würth Elektronik

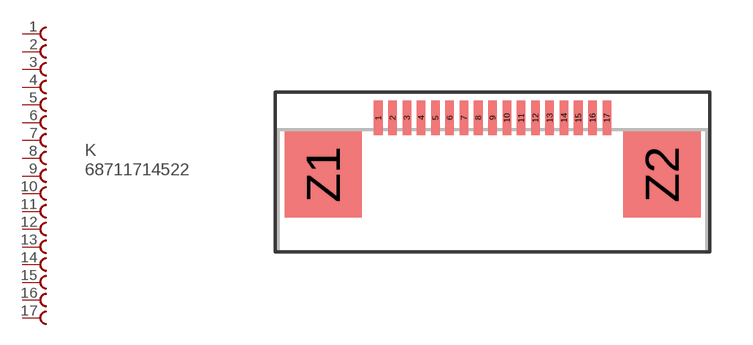
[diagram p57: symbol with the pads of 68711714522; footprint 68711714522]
Designator prefix K

## 68711714522  [68711714522]
1  1  pas
2  2  pas
3  3  pas
4  4  pas
5  5  pas
6  6  pas
7  7  pas
8  8  pas
9  9  pas
10  10  pas
11  11  pas
12  12  pas
13  13  pas
14  14  pas
15  15  pas
16  16  pas
17  17  pas

## Footprint 68711714522 (pad centres in mm)
WE-FPC 0.5mm SMT ZIF Horizontal Bottom Contact, 17 Pins
smd 0.3 x 1.2: 1 -3.75,0.6; 2 -3.25,0.6; 3 -2.75,0.6; 4 -2.25,0.6; 5 -1.75,0.6; 6 -1.25,0.6; 7 -0.75,0.6; 8 -0.25,0.6; 9 0.25,0.6; 10 0.75,0.6; 11 1.25,0.6; 12 1.75,0.6; 13 2.25,0.6; 14 2.75,0.6; 15 3.25,0.6; 16 3.75,0.6; 17 4.25,0.6
smd 2.7 x 3: Z1 -5.68,-1.38; Z2 6.18,-1.38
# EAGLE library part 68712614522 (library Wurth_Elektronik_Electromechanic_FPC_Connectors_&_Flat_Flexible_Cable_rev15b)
WE-FPC 0.5mm SMT ZIF Horizontal Bottom Contact, 26 Pins=>Code : Con_FPC_ZIF_0.50_68712614522 Details see: http://katalog.we-online.de/en/em/687_1xx_145_22 Created 2014-07-09, Karrer Zheng 2014 (C) Würth Elektronik

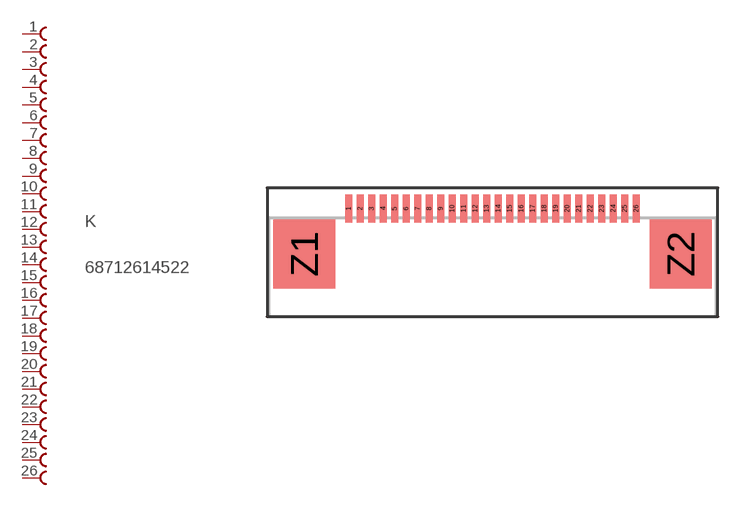
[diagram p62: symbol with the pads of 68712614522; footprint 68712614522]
Designator prefix K

## 68712614522  [68712614522]
1  1  pas
2  2  pas
3  3  pas
4  4  pas
5  5  pas
6  6  pas
7  7  pas
8  8  pas
9  9  pas
10  10  pas
11  11  pas
12  12  pas
13  13  pas
14  14  pas
15  15  pas
16  16  pas
17  17  pas
18  18  pas
19  19  pas
20  20  pas
21  21  pas
22  22  pas
23  23  pas
24  24  pas
25  25  pas
26  26  pas

## Footprint 68712614522 (pad centres in mm)
WE-FPC 0.5mm SMT ZIF Horizontal Bottom Contact, 26 Pins
smd 0.3 x 1.2: 1 -6.25,0.6; 2 -5.75,0.6; 3 -5.25,0.6; 4 -4.75,0.6; 5 -4.25,0.6; 6 -3.75,0.6; 7 -3.25,0.6; 8 -2.75,0.6; 9 -2.25,0.6; 10 -1.75,0.6; 11 -1.25,0.6; 12 -0.75,0.6; 13 -0.25,0.6; 14 0.25,0.6; 15 0.75,0.6; 16 1.25,0.6; 17 1.75,0.6; 18 2.25,0.6; 19 2.75,0.6; 20 3.25,0.6; 21 3.75,0.6; 22 4.25,0.6; 23 4.75,0.6; 24 5.25,0.6; 25 5.75,0.6; 26 6.25,0.6
smd 2.7 x 3: Z1 -8.18,-1.38; Z2 8.18,-1.38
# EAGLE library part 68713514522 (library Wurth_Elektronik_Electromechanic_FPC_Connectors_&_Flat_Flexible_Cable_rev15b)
WR-FPC 0.5mm SMT ZIF Horizontal Bottom Contact, 35 Pins=>Code : Con_FPC_ZIF_0.50_68713514522 Details see: http://katalog.we-online.de/en/em/687_1xx_145_22 Created 2014-07-09, Karrer Zheng 2014 (C) Würth Elektronik

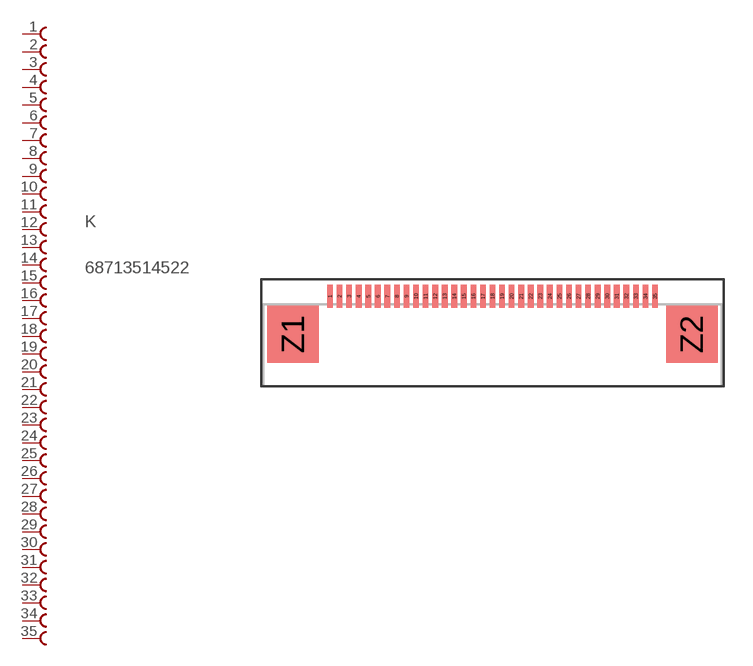
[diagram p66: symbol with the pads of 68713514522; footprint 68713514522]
Designator prefix K

## 68713514522  [68713514522]
1  1  pas
2  2  pas
3  3  pas
4  4  pas
5  5  pas
6  6  pas
7  7  pas
8  8  pas
9  9  pas
10  10  pas
11  11  pas
12  12  pas
13  13  pas
14  14  pas
15  15  pas
16  16  pas
17  17  pas
18  18  pas
19  19  pas
20  20  pas
21  21  pas
22  22  pas
23  23  pas
24  24  pas
25  25  pas
26  26  pas
27  27  pas
28  28  pas
29  29  pas
30  30  pas
31  31  pas
32  32  pas
33  33  pas
34  34  pas
35  35  pas

## Footprint 68713514522 (pad centres in mm)
WR-FPC 0.5mm SMT ZIF Horizontal Bottom Contact, 35 Pins
smd 0.3 x 1.2: 1 -8.25,0.6; 2 -7.75,0.6; 3 -7.25,0.6; 4 -6.75,0.6; 5 -6.25,0.6; 6 -5.75,0.6; 7 -5.25,0.6; 8 -4.75,0.6; 9 -4.25,0.6; 10 -3.75,0.6; 11 -3.25,0.6; 12 -2.75,0.6; 13 -2.25,0.6; 14 -1.75,0.6; 15 -1.25,0.6; 16 -0.75,0.6; 17 -0.25,0.6; 18 0.25,0.6; 19 0.75,0.6; 20 1.25,0.6; 21 1.75,0.6; 22 2.25,0.6; 23 2.75,0.6; 24 3.25,0.6; 25 3.75,0.6; 26 4.25,0.6; 27 4.75,0.6; 28 5.25,0.6; 29 5.75,0.6; 30 6.25,0.6; 31 6.75,0.6; 32 7.25,0.6; 33 7.75,0.6; 34 8.25,0.6; 35 8.75,0.6
smd 2.7 x 3: Z1 -10.18,-1.38; Z2 10.68,-1.38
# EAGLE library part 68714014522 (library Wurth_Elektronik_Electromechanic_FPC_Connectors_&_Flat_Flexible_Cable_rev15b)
WR-FPC 0.5mm SMT ZIF Horizontal Bottom Contact, 40 Pins=>Code : Con_FPC_ZIF_0.50_68714014522 Details see: http://katalog.we-online.de/en/em/687_1xx_145_22 Created 2014-07-09, Karrer Zheng 2014 (C) Würth Elektronik

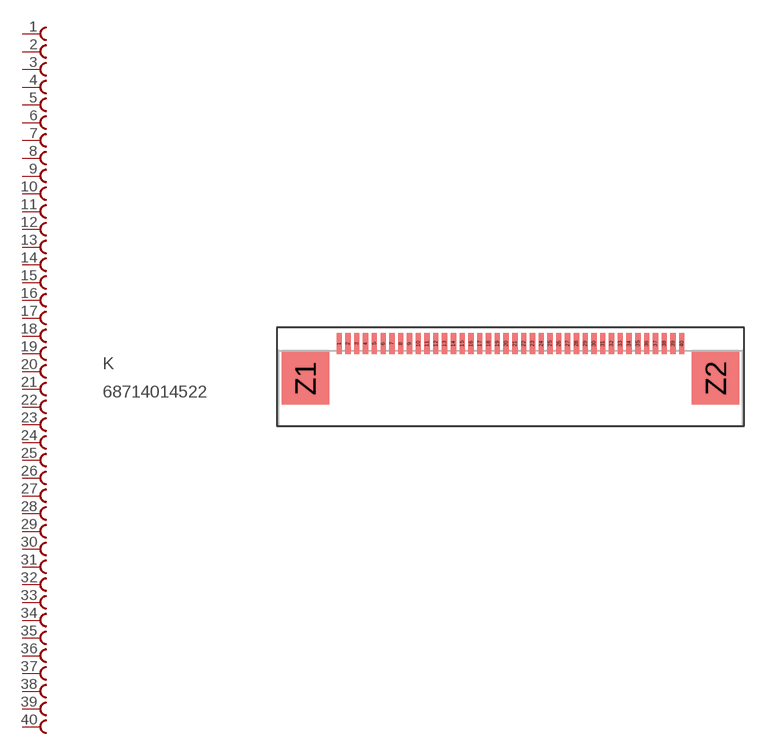
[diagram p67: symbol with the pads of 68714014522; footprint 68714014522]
Designator prefix K

## 68714014522  [68714014522]
1  1  pas
2  2  pas
3  3  pas
4  4  pas
5  5  pas
6  6  pas
7  7  pas
8  8  pas
9  9  pas
10  10  pas
11  11  pas
12  12  pas
13  13  pas
14  14  pas
15  15  pas
16  16  pas
17  17  pas
18  18  pas
19  19  pas
20  20  pas
21  21  pas
22  22  pas
23  23  pas
24  24  pas
25  25  pas
26  26  pas
27  27  pas
28  28  pas
29  29  pas
30  30  pas
31  31  pas
32  32  pas
33  33  pas
34  34  pas
35  35  pas
36  36  pas
37  37  pas
38  38  pas
39  39  pas
40  40  pas

## Footprint 68714014522 (pad centres in mm)
WR-FPC 0.5mm SMT ZIF Horizontal Bottom Contact, 40 Pins
smd 0.3 x 1.2: 1 -9.75,0.6; 2 -9.25,0.6; 3 -8.75,0.6; 4 -8.25,0.6; 5 -7.75,0.6; 6 -7.25,0.6; 7 -6.75,0.6; 8 -6.25,0.6; 9 -5.75,0.6; 10 -5.25,0.6; 11 -4.75,0.6; 12 -4.25,0.6; 13 -3.75,0.6; 14 -3.25,0.6; 15 -2.75,0.6; 16 -2.25,0.6; 17 -1.75,0.6; 18 -1.25,0.6; 19 -0.75,0.6; 20 -0.25,0.6; 21 0.25,0.6; 22 0.75,0.6; 23 1.25,0.6; 24 1.75,0.6; 25 2.25,0.6; 26 2.75,0.6; 27 3.25,0.6; 28 3.75,0.6; 29 4.25,0.6; 30 4.75,0.6; 31 5.25,0.6; 32 5.75,0.6; 33 6.25,0.6; 34 6.75,0.6; 35 7.25,0.6; 36 7.75,0.6; 37 8.25,0.6; 38 8.75,0.6; 39 9.25,0.6; 40 9.75,0.6
smd 2.7 x 3: Z1 -11.68,-1.38; Z2 11.68,-1.38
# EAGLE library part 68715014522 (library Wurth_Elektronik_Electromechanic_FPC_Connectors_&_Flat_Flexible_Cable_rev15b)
WR-FPC 0.5mm SMT ZIF Horizontal Bottom Contact, 50 Pins=>Code : Con_FPC_ZIF_0.50_68715014522 Details see: http://katalog.we-online.de/en/em/687_1xx_145_22 Created 2014-07-09, Karrer Zheng 2014 (C) Würth Elektronik

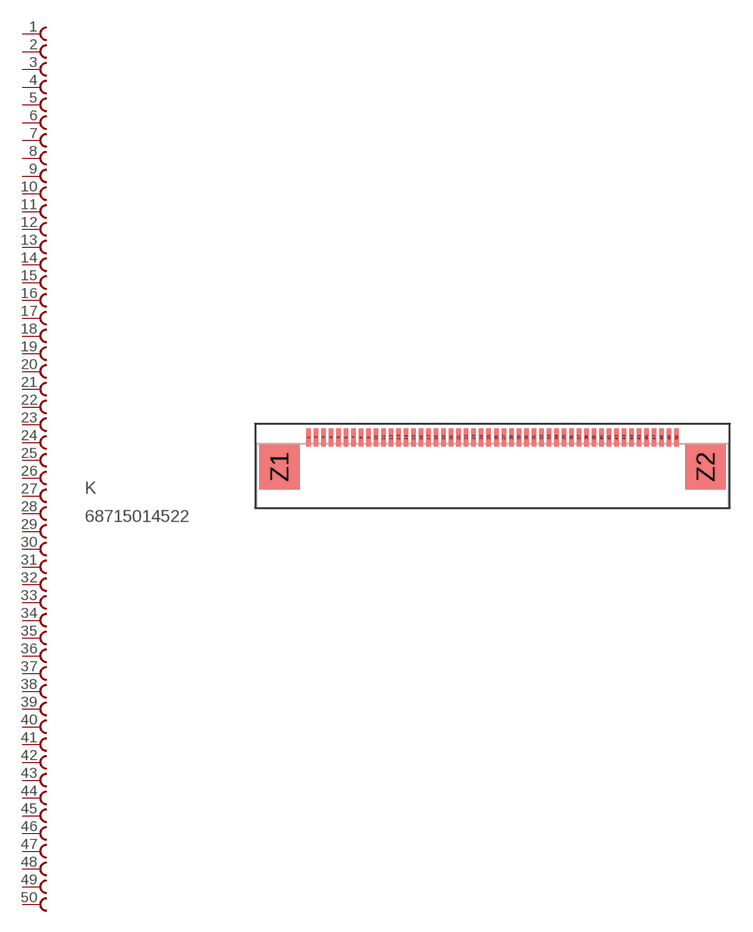
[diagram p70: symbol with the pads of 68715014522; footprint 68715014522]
Designator prefix K

## 68715014522  [68715014522]
1  1  pas
2  2  pas
3  3  pas
4  4  pas
5  5  pas
6  6  pas
7  7  pas
8  8  pas
9  9  pas
10  10  pas
11  11  pas
12  12  pas
13  13  pas
14  14  pas
15  15  pas
16  16  pas
17  17  pas
18  18  pas
19  19  pas
20  20  pas
21  21  pas
22  22  pas
23  23  pas
24  24  pas
25  25  pas
26  26  pas
27  27  pas
28  28  pas
29  29  pas
30  30  pas
31  31  pas
32  32  pas
33  33  pas
34  34  pas
35  35  pas
36  36  pas
37  37  pas
38  38  pas
39  39  pas
40  40  pas
41  41  pas
42  42  pas
43  43  pas
44  44  pas
45  45  pas
46  46  pas
47  47  pas
48  48  pas
49  49  pas
50  50  pas

## Footprint 68715014522 (pad centres in mm)
WR-FPC 0.5mm SMT ZIF Horizontal Bottom Contact, 50 Pins
smd 0.3 x 1.2: 1 -12.25,0.6; 2 -11.75,0.6; 3 -11.25,0.6; 4 -10.75,0.6; 5 -10.25,0.6; 6 -9.75,0.6; 7 -9.25,0.6; 8 -8.75,0.6; 9 -8.25,0.6; 10 -7.75,0.6; 11 -7.25,0.6; 12 -6.75,0.6; 13 -6.25,0.6; 14 -5.75,0.6; 15 -5.25,0.6; 16 -4.75,0.6; 17 -4.25,0.6; 18 -3.75,0.6; 19 -3.25,0.6; 20 -2.75,0.6; 21 -2.25,0.6; 22 -1.75,0.6; 23 -1.25,0.6; 24 -0.75,0.6; 25 -0.25,0.6; 26 0.25,0.6; 27 0.75,0.6; 28 1.25,0.6; 29 1.75,0.6; 30 2.25,0.6; 31 2.75,0.6; 32 3.25,0.6; 33 3.75,0.6; 34 4.25,0.6; 35 4.75,0.6; 36 5.25,0.6; 37 5.75,0.6; 38 6.25,0.6; 39 6.75,0.6; 40 7.25,0.6; 41 7.75,0.6; 42 8.25,0.6; 43 8.75,0.6; 44 9.25,0.6; 45 9.75,0.6; 46 10.25,0.6; 47 10.75,0.6; 48 11.25,0.6; 49 11.75,0.6; 50 12.25,0.6
smd 2.7 x 3: Z1 -14.18,-1.38; Z2 14.18,-1.38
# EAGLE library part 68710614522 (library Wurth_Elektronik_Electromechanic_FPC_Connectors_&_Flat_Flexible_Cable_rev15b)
WE-FPC 0.5mm SMT ZIF Horizontal Bottom Contact, 6 Pins=>Code : Con_FPC_ZIF_0.50_68710614522 Details see: http://katalog.we-online.de/en/em/687_1xx_145_22 Created 2014-07-09, Karrer Zheng 2014 (C) Würth Elektronik

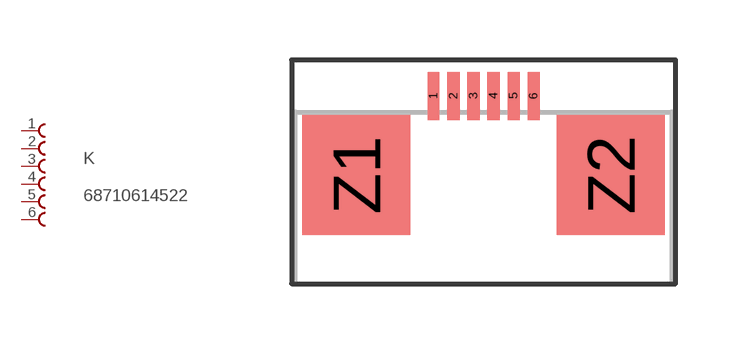
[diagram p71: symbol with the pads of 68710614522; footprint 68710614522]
Designator prefix K

## 68710614522  [68710614522]
1  1  pas
2  2  pas
3  3  pas
4  4  pas
5  5  pas
6  6  pas

## Footprint 68710614522 (pad centres in mm)
WE-FPC 0.5mm SMT ZIF Horizontal Bottom Contact, 6 Pins
smd 0.3 x 1.2: 1 -1.25,0.6; 2 -0.75,0.6; 3 -0.25,0.6; 4 0.25,0.6; 5 0.75,0.6; 6 1.25,0.6
smd 2.7 x 3: Z1 -3.18,-1.38; Z2 3.18,-1.38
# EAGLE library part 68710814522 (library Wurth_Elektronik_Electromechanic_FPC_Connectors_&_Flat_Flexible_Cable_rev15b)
WE-FPC 0.5mm SMT ZIF Horizontal Bottom Contact, 8 Pins=>Code : Con_FPC_ZIF_0.50_68710814522 Details see: http://katalog.we-online.de/en/em/687_1xx_145_22 Created 2014-07-09, Karrer Zheng 2014 (C) Würth Elektronik

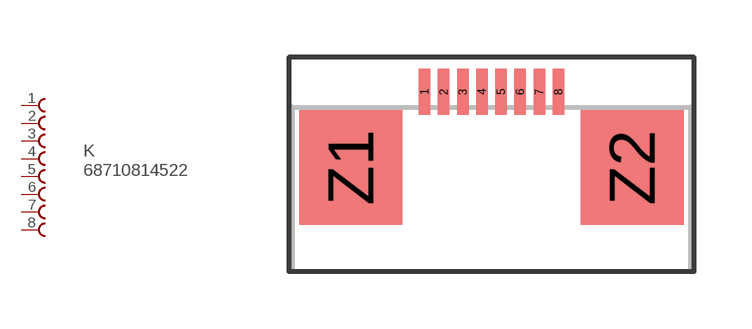
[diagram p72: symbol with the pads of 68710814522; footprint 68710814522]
Designator prefix K

## 68710814522  [68710814522]
1  1  pas
2  2  pas
3  3  pas
4  4  pas
5  5  pas
6  6  pas
7  7  pas
8  8  pas

## Footprint 68710814522 (pad centres in mm)
WE-FPC 0.5mm SMT ZIF Horizontal Bottom Contact, 8 Pins
smd 0.3 x 1.2: 1 -1.75,0.6; 2 -1.25,0.6; 3 -0.75,0.6; 4 -0.25,0.6; 5 0.25,0.6; 6 0.75,0.6; 7 1.25,0.6; 8 1.75,0.6
smd 2.7 x 3: Z1 -3.68,-1.38; Z2 3.68,-1.38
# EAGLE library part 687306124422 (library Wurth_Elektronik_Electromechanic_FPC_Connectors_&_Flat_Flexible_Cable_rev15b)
WR-FPC-0.50mm SMT ZIF Vertical Type A,pins 6 Pins =>Code : Con_FPC_ZIF_0.50_687306124422 Details see: http://katalog.we-online.de/en/em/687_3xx_124_422 Created 2014-07-09, Karrer Zheng 2014 (C) Würth Elektronik

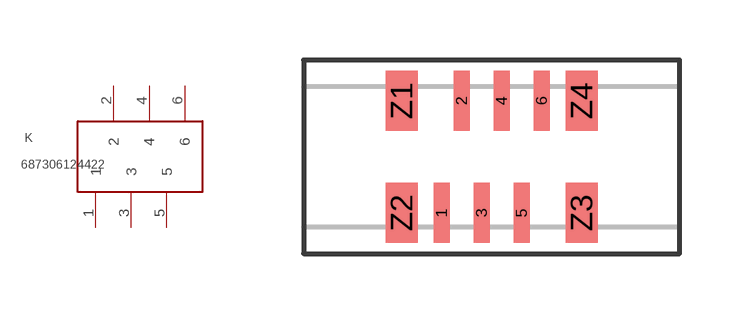
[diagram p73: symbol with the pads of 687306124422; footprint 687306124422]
Designator prefix K

## 687306124422  [687306124422]
1  1
2  2
3  3
4  4
5  5
6  6

## Footprint 687306124422 (pad centres in mm)
WR-FPC-0.50mm SMT ZIF Vertical Type A,pins 6
smd 0.4 x 1.5: 1 -1.25,-1.4; 2 -0.75,1.4; 3 -0.25,-1.4; 4 0.25,1.4; 5 0.75,-1.4; 6 1.25,1.4
smd 0.8 x 1.5: Z1 -2.25,1.4; Z2 -2.25,-1.4; Z3 2.25,-1.4; Z4 2.25,1.4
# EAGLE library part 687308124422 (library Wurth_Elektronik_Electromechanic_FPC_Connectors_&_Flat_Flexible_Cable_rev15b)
WR-FPC-0.50mm SMT ZIF Vertical Type A,pins 8 Pins=>Code : Con_FPC_ZIF_0.50_687308124422 Details see: http://katalog.we-online.de/en/em/687_3xx_124_422 Created 2014-07-09, Karrer Zheng 2014 (C) Würth Elektronik

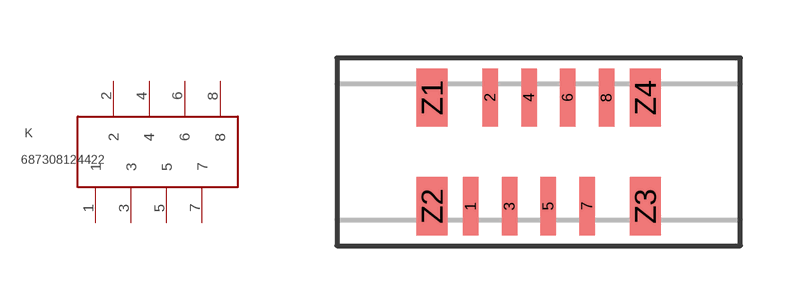
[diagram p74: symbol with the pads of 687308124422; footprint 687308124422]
Designator prefix K

## 687308124422  [687308124422]
1  1
2  2
3  3
4  4
5  5
6  6
7  7
8  8

## Footprint 687308124422 (pad centres in mm)
WR-FPC-0.50mm SMT ZIF Vertical Type A,pins 8
smd 0.4 x 1.5: 1 -1,-1.4; 2 -0.5,1.4; 3 0,-1.4; 4 0.5,1.4; 5 1,-1.4; 6 1.5,1.4; 7 2,-1.4; 8 2.5,1.4
smd 0.8 x 1.5: Z1 -2,1.4; Z2 -2,-1.4; Z3 3.5,-1.4; Z4 3.5,1.4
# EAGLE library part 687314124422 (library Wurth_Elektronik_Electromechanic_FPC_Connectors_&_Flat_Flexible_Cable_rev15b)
WR-FPC-0.50mm SMT ZIF Vertical Type A,pins 14 Pins=>Code : Con_FPC_ZIF_0.50_687314124422 Details see: http://katalog.we-online.de/en/em/687_3xx_124_422 Created 2014-07-09, Karrer Zheng 2014 (C) Würth Elektronik

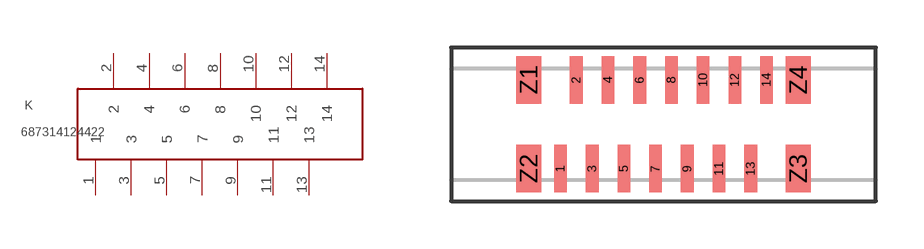
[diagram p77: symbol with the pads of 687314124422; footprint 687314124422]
Designator prefix K

## 687314124422  [687314124422]
1  1
2  2
3  3
4  4
5  5
6  6
7  7
8  8
9  9
10  10
11  11
12  12
13  13
14  14

## Footprint 687314124422 (pad centres in mm)
WR-FPC-0.50mm SMT ZIF Vertical Type A,pins 14
smd 0.4 x 1.5: 1 -2.27,-1.4; 2 -1.77,1.4; 3 -1.27,-1.4; 4 -0.77,1.4; 5 -0.27,-1.4; 6 0.23,1.4; 7 0.73,-1.4; 8 1.23,1.4; 9 1.73,-1.4; 10 2.23,1.4; 11 2.73,-1.4; 12 3.23,1.4; 13 3.73,-1.4; 14 4.23,1.4
smd 0.8 x 1.5: Z1 -3.27,1.4; Z2 -3.27,-1.4; Z3 5.23,-1.4; Z4 5.23,1.4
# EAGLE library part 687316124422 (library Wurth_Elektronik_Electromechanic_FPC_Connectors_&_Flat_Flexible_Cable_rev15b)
WR-FPC-0.50mm SMT ZIF Vertical Type A,pins 16 Pins =>Code : Con_FPC_ZIF_0.50_687316124422 Details see: http://katalog.we-online.de/en/em/687_3xx_124_422 Created 2014-07-09, Karrer Zheng 2014 (C) Würth Elektronik

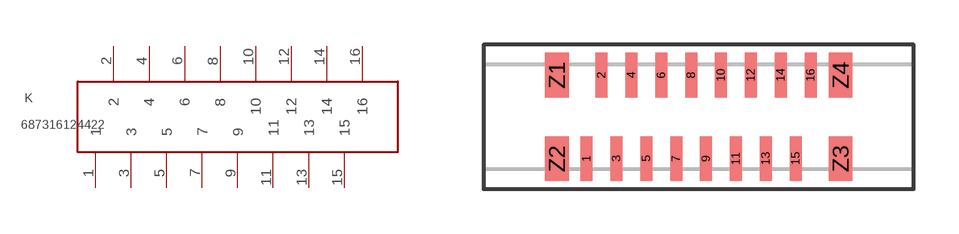
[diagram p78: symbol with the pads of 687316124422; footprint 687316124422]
Designator prefix K

## 687316124422  [687316124422]
1  1
2  2
3  3
4  4
5  5
6  6
7  7
8  8
9  9
10  10
11  11
12  12
13  13
14  14
15  15
16  16

## Footprint 687316124422 (pad centres in mm)
WR-FPC-0.50mm SMT ZIF Vertical Type A,pins 16
smd 0.4 x 1.5: 1 -3.54,-1.4; 2 -3.04,1.4; 3 -2.54,-1.4; 4 -2.04,1.4; 5 -1.54,-1.4; 6 -1.04,1.4; 7 -0.54,-1.4; 8 -0.04,1.4; 9 0.46,-1.4; 10 0.96,1.4; 11 1.46,-1.4; 12 1.96,1.4; 13 2.46,-1.4; 14 2.96,1.4; 15 3.46,-1.4; 16 3.96,1.4
smd 0.8 x 1.5: Z1 -4.54,1.4; Z2 -4.54,-1.4; Z3 4.96,-1.4; Z4 4.96,1.4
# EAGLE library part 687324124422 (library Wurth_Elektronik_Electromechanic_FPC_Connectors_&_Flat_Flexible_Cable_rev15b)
WR-FPC-0.50mm SMT ZIF Vertical Type A,pins 24 Pins =>Code : Con_FPC_ZIF_0.50_687324124422 Details see: http://katalog.we-online.de/en/em/687_3xx_124_422 Created 2014-07-09, Karrer Zheng 2014 (C) Würth Elektronik

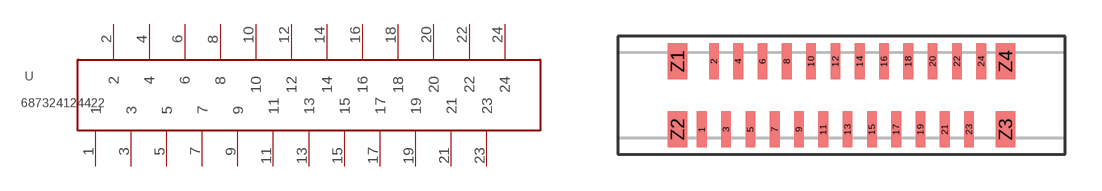
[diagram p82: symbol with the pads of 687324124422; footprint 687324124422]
Designator prefix -

## 687324124422  [687324124422]
1  1
2  2
3  3
4  4
5  5
6  6
7  7
8  8
9  9
10  10
11  11
12  12
13  13
14  14
15  15
16  16
17  17
18  18
19  19
20  20
21  21
22  22
23  23
24  24

## Footprint 687324124422 (pad centres in mm)
WR-FPC-0.50mm SMT ZIF Vertical Type A,pins 24
smd 0.4 x 1.5: 1 -4.81,-1.4; 2 -4.31,1.4; 3 -3.81,-1.4; 4 -3.31,1.4; 5 -2.81,-1.4; 6 -2.31,1.4; 7 -1.81,-1.4; 8 -1.31,1.4; 9 -0.81,-1.4; 10 -0.31,1.4; 11 0.19,-1.4; 12 0.69,1.4; 13 1.19,-1.4; 14 1.69,1.4; 15 2.19,-1.4; 16 2.69,1.4; 17 3.19,-1.4; 18 3.69,1.4; 19 4.19,-1.4; 20 4.69,1.4; 21 5.19,-1.4; 22 5.69,1.4; 23 6.19,-1.4; 24 6.69,1.4
smd 0.8 x 1.5: Z1 -5.81,1.4; Z2 -5.81,-1.4; Z3 7.69,-1.4; Z4 7.69,1.4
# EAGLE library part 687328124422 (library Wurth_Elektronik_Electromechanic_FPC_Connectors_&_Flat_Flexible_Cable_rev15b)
WR-FPC-0.50mm SMT ZIF Vertical Type A,pins 28 Pins=>Code : Con_FPC_ZIF_0.50_687328124422 Details see: http://katalog.we-online.de/en/em/687_3xx_124_422 Created 2014-07-09, Karrer Zheng 2014 (C) Würth Elektronik

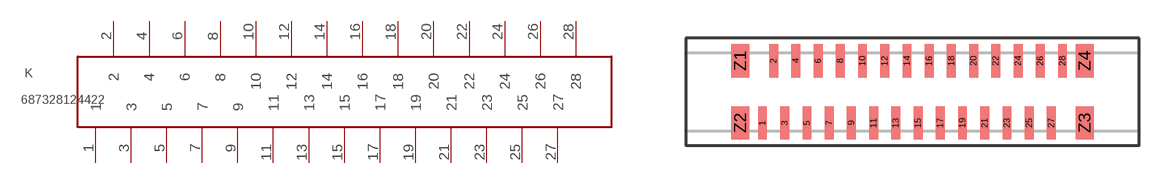
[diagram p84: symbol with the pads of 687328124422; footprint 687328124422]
Designator prefix K

## 687328124422  [687328124422]
1  1
2  2
3  3
4  4
5  5
6  6
7  7
8  8
9  9
10  10
11  11
12  12
13  13
14  14
15  15
16  16
17  17
18  18
19  19
20  20
21  21
22  22
23  23
24  24
25  25
26  26
27  27
28  28

## Footprint 687328124422 (pad centres in mm)
WR-FPC-0.50mm SMT ZIF Vertical Type A,pins 28
smd 0.4 x 1.5: 1 -6.08,-1.4; 2 -5.58,1.4; 3 -5.08,-1.4; 4 -4.58,1.4; 5 -4.08,-1.4; 6 -3.58,1.4; 7 -3.08,-1.4; 8 -2.58,1.4; 9 -2.08,-1.4; 10 -1.58,1.4; 11 -1.08,-1.4; 12 -0.58,1.4; 13 -0.08,-1.4; 14 0.42,1.4; 15 0.92,-1.4; 16 1.42,1.4; 17 1.92,-1.4; 18 2.42,1.4; 19 2.92,-1.4; 20 3.42,1.4; 21 3.92,-1.4; 22 4.42,1.4; 23 4.92,-1.4; 24 5.42,1.4; 25 5.92,-1.4; 26 6.42,1.4; 27 6.92,-1.4; 28 7.42,1.4
smd 0.8 x 1.5: Z1 -7.08,1.4; Z2 -7.08,-1.4; Z3 8.42,-1.4; Z4 8.42,1.4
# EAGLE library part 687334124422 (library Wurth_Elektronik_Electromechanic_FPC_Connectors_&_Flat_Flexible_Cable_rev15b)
WR-FPC-0.50mm SMT ZIF Vertical Type A,pins 34 Pins =>Code : Con_FPC_ZIF_0.50_687334124422 Details see: http://katalog.we-online.de/en/em/687_3xx_124_422 Created 2014-07-09, Karrer Zheng 2014 (C) Würth Elektronik

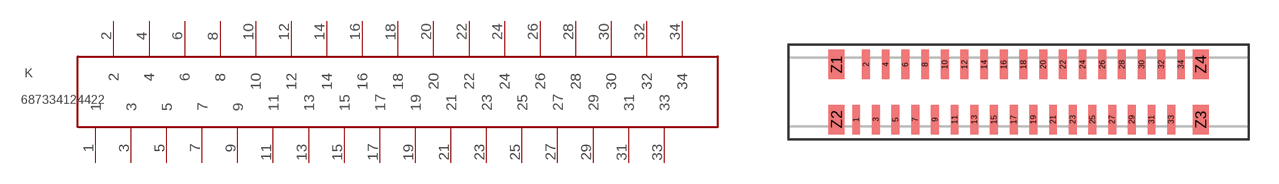
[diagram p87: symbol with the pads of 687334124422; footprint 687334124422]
Designator prefix K

## 687334124422  [687334124422]
1  1
2  2
3  3
4  4
5  5
6  6
7  7
8  8
9  9
10  10
11  11
12  12
13  13
14  14
15  15
16  16
17  17
18  18
19  19
20  20
21  21
22  22
23  23
24  24
25  25
26  26
27  27
28  28
29  29
30  30
31  31
32  32
33  33
34  34

## Footprint 687334124422 (pad centres in mm)
WR-FPC-0.50mm SMT ZIF Vertical Type A,pins 34
smd 0.4 x 1.5: 1 -7.35,-1.4; 2 -6.85,1.4; 3 -6.35,-1.4; 4 -5.85,1.4; 5 -5.35,-1.4; 6 -4.85,1.4; 7 -4.35,-1.4; 8 -3.85,1.4; 9 -3.35,-1.4; 10 -2.85,1.4; 11 -2.35,-1.4; 12 -1.85,1.4; 13 -1.35,-1.4; 14 -0.85,1.4; 15 -0.35,-1.4; 16 0.15,1.4; 17 0.65,-1.4; 18 1.15,1.4; 19 1.65,-1.4; 20 2.15,1.4; 21 2.65,-1.4; 22 3.15,1.4; 23 3.65,-1.4; 24 4.15,1.4; 25 4.65,-1.4; 26 5.15,1.4; 27 5.65,-1.4; 28 6.15,1.4; 29 6.65,-1.4; 30 7.15,1.4; 31 7.65,-1.4; 32 8.15,1.4; 33 8.65,-1.4; 34 9.15,1.4
smd 0.8 x 1.5: Z1 -8.35,1.4; Z2 -8.35,-1.4; Z3 10.15,-1.4; Z4 10.15,1.4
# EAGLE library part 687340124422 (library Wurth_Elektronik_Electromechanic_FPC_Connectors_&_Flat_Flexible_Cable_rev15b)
WR-FPC-0.50mm SMT ZIF Vertical Type A,pins 40 Pins=>Code : Con_FPC_ZIF_0.50_687340124422 Details see: http://katalog.we-online.de/en/em/687_3xx_124_422 Created 2014-07-09, Karrer Zheng 2014 (C) Würth Elektronik

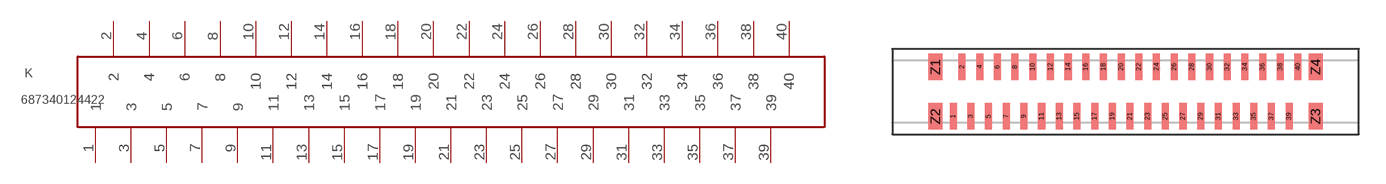
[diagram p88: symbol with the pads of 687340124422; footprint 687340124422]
Designator prefix K

## 687340124422  [687340124422]
1  1
2  2
3  3
4  4
5  5
6  6
7  7
8  8
9  9
10  10
11  11
12  12
13  13
14  14
15  15
16  16
17  17
18  18
19  19
20  20
21  21
22  22
23  23
24  24
25  25
26  26
27  27
28  28
29  29
30  30
31  31
32  32
33  33
34  34
35  35
36  36
37  37
38  38
39  39
40  40

## Footprint 687340124422 (pad centres in mm)
WR-FPC-0.50mm SMT ZIF Vertical Type A,pins 40
smd 0.4 x 1.5: 1 -8.62,-1.4; 2 -8.12,1.4; 3 -7.62,-1.4; 4 -7.12,1.4; 5 -6.62,-1.4; 6 -6.12,1.4; 7 -5.62,-1.4; 8 -5.12,1.4; 9 -4.62,-1.4; 10 -4.12,1.4; 11 -3.62,-1.4; 12 -3.12,1.4; 13 -2.62,-1.4; 14 -2.12,1.4; 15 -1.62,-1.4; 16 -1.12,1.4; 17 -0.62,-1.4; 18 -0.12,1.4; 19 0.38,-1.4; 20 0.88,1.4; 21 1.38,-1.4; 22 1.88,1.4; 23 2.38,-1.4; 24 2.88,1.4; 25 3.38,-1.4; 26 3.88,1.4; 27 4.38,-1.4; 28 4.88,1.4; 29 5.38,-1.4; 30 5.88,1.4; 31 6.38,-1.4; 32 6.88,1.4; 33 7.38,-1.4; 34 7.88,1.4; 35 8.38,-1.4; 36 8.88,1.4; 37 9.38,-1.4; 38 9.88,1.4; 39 10.38,-1.4; 40 10.88,1.4
smd 0.8 x 1.5: Z1 -9.62,1.4; Z2 -9.62,-1.4; Z3 11.88,-1.4; Z4 11.88,1.4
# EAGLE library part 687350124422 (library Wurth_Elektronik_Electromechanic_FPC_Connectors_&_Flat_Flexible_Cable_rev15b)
WR-FPC-0.50mm SMT ZIF Vertical Type A,pins 50 Pins=>Code : Con_FPC_ZIF_0.50_687350124422 Details see: http://katalog.we-online.de/en/em/687_3xx_124_422 Created 2014-07-09, Karrer Zheng 2014 (C) Würth Elektronik

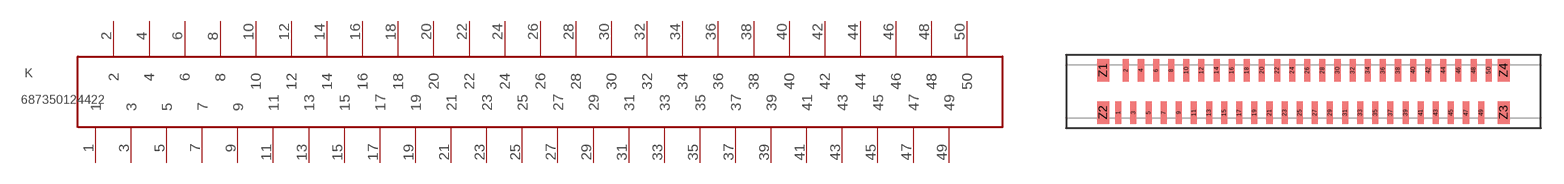
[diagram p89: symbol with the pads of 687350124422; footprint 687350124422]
Designator prefix K

## 687350124422  [687350124422]
1  1
2  2
3  3
4  4
5  5
6  6
7  7
8  8
9  9
10  10
11  11
12  12
13  13
14  14
15  15
16  16
17  17
18  18
19  19
20  20
21  21
22  22
23  23
24  24
25  25
26  26
27  27
28  28
29  29
30  30
31  31
32  32
33  33
34  34
35  35
36  36
37  37
38  38
39  39
40  40
41  41
42  42
43  43
44  44
45  45
46  46
47  47
48  48
49  49
50  50

## Footprint 687350124422 (pad centres in mm)
WR-FPC-0.50mm SMT ZIF Vertical Type A,pins 50
smd 0.4 x 1.5: 1 -9.89,-1.4; 2 -9.39,1.4; 3 -8.89,-1.4; 4 -8.39,1.4; 5 -7.89,-1.4; 6 -7.39,1.4; 7 -6.89,-1.4; 8 -6.39,1.4; 9 -5.89,-1.4; 10 -5.39,1.4; 11 -4.89,-1.4; 12 -4.39,1.4; 13 -3.89,-1.4; 14 -3.39,1.4; 15 -2.89,-1.4; 16 -2.39,1.4; 17 -1.89,-1.4; 18 -1.39,1.4; 19 -0.89,-1.4; 20 -0.39,1.4; 21 0.11,-1.4; 22 0.61,1.4; 23 1.11,-1.4; 24 1.61,1.4; 25 2.11,-1.4; 26 2.61,1.4; 27 3.11,-1.4; 28 3.61,1.4; 29 4.11,-1.4; 30 4.61,1.4; 31 5.11,-1.4; 32 5.61,1.4; 33 6.11,-1.4; 34 6.61,1.4; 35 7.11,-1.4; 36 7.61,1.4; 37 8.11,-1.4; 38 8.61,1.4; 39 9.11,-1.4; 40 9.61,1.4; 41 10.11,-1.4; 42 10.61,1.4; 43 11.11,-1.4; 44 11.61,1.4; 45 12.11,-1.4; 46 12.61,1.4; 47 13.11,-1.4; 48 13.61,1.4; 49 14.11,-1.4; 50 14.61,1.4
smd 0.8 x 1.5: Z1 -10.89,1.4; Z2 -10.89,-1.4; Z3 15.61,-1.4; Z4 15.61,1.4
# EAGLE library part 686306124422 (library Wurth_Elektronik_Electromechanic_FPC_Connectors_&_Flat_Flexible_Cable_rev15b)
WR-FPC-1.00mm SMT ZIF Vertical Type A,6 pins=>Code : Con_FPC_ZIF_1.00_686306124422 Details see: http://katalog.we-online.de/en/em/686_3xx_124_422 Created 2014-07-09, Karrer Zheng 2014 (C) Würth Elektronik

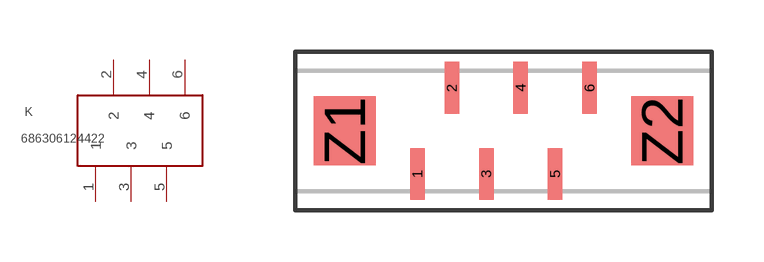
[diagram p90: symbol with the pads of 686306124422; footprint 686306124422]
Designator prefix K

## 686306124422  [686306124422]
1  1
2  2
3  3
4  4
5  5
6  6

## Footprint 686306124422 (pad centres in mm)
WR-FPC-1.00mm SMT ZIF Vertical Type A,6 pins
smd 0.42 x 1.5: 1 -1.5,-1.25; 2 -0.5,1.25; 3 0.5,-1.25; 4 1.5,1.25; 5 2.5,-1.25; 6 3.5,1.25
smd 1.8 x 2: Z1 -3.61,0; Z2 5.61,0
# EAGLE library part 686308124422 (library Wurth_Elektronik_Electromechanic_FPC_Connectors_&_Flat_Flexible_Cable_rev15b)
WR-FPC-1.00mm SMT ZIF Vertical Type A,8 pins=>Code : Con_FPC_ZIF_1.00_686308124422 Details see: http://katalog.we-online.de/en/em/686_3xx_124_422 Created 2014-07-09, Karrer Zheng 2014 (C) Würth Elektronik

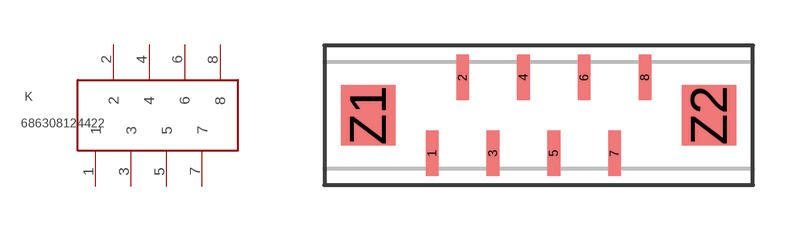
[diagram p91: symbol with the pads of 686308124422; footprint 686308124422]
Designator prefix K

## 686308124422  [686308124422]
1  1
2  2
3  3
4  4
5  5
6  6
7  7
8  8

## Footprint 686308124422 (pad centres in mm)
WR-FPC-1.00mm SMT ZIF Vertical Type A,8 pins
smd 0.42 x 1.5: 1 -2.77,-1.25; 2 -1.77,1.25; 3 -0.77,-1.25; 4 0.23,1.25; 5 1.23,-1.25; 6 2.23,1.25; 7 3.23,-1.25; 8 4.23,1.25
smd 1.8 x 2: Z1 -4.88,0; Z2 6.34,0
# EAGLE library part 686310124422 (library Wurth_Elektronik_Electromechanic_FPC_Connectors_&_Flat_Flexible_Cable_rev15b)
WR-FPC-1.00mm SMT ZIF Vertical Type A,10 pins=>Code : Con_FPC_ZIF_1.00_686310124422 Details see: http://katalog.we-online.de/en/em/686_3xx_124_422 Created 2014-07-09, Karrer Zheng 2014 (C) Würth Elektronik

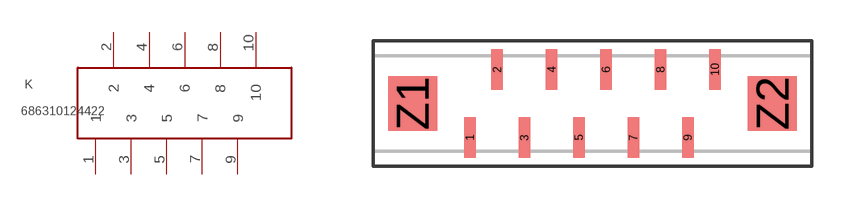
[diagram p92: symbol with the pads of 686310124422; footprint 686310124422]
Designator prefix K

## 686310124422  [686310124422]
1  1
2  2
3  3
4  4
5  5
6  6
7  7
8  8
9  9
10  10

## Footprint 686310124422 (pad centres in mm)
WR-FPC-1.00mm SMT ZIF Vertical Type A,10 pins
smd 0.42 x 1.5: 1 -4.04,-1.25; 2 -3.04,1.25; 3 -2.04,-1.25; 4 -1.04,1.25; 5 -0.04,-1.25; 6 0.96,1.25; 7 1.96,-1.25; 8 2.96,1.25; 9 3.96,-1.25; 10 4.96,1.25
smd 1.8 x 2: Z1 -6.15,0; Z2 7.07,0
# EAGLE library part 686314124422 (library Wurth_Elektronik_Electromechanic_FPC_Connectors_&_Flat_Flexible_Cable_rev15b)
WR-FPC-1.00mm SMT ZIF Vertical Type A,14 pins=>Code : Con_FPC_ZIF_1.00_686314124422 Details see: http://katalog.we-online.de/en/em/686_3xx_124_422 Created 2014-07-09, Karrer Zheng 2014 (C) Würth Elektronik

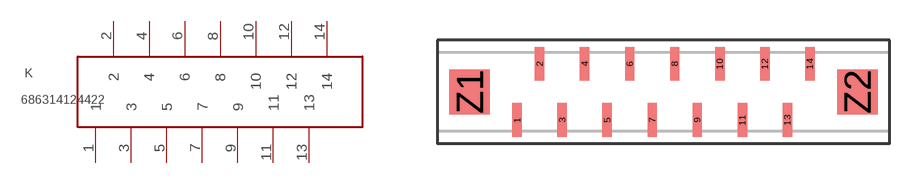
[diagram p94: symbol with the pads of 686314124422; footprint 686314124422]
Designator prefix K

## 686314124422  [686314124422]
1  1
2  2
3  3
4  4
5  5
6  6
7  7
8  8
9  9
10  10
11  11
12  12
13  13
14  14

## Footprint 686314124422 (pad centres in mm)
WR-FPC-1.00mm SMT ZIF Vertical Type A,14 pins
smd 0.42 x 1.5: 1 -5.31,-1.25; 2 -4.31,1.25; 3 -3.31,-1.25; 4 -2.31,1.25; 5 -1.31,-1.25; 6 -0.31,1.25; 7 0.69,-1.25; 8 1.69,1.25; 9 2.69,-1.25; 10 3.69,1.25; 11 4.69,-1.25; 12 5.69,1.25; 13 6.69,-1.25; 14 7.69,1.25
smd 1.8 x 2: Z1 -7.42,0; Z2 9.8,0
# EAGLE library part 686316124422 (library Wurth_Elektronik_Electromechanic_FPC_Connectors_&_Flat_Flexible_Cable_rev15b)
WR-FPC-1.00mm SMT ZIF Vertical Type A,16 pins=>Code : Con_FPC_ZIF_1.00_686316124422 Details see: http://katalog.we-online.de/en/em/686_3xx_124_422 Created 2014-07-09, Karrer Zheng 2014 (C) Würth Elektronik

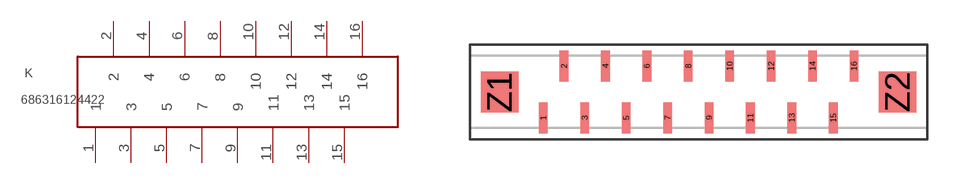
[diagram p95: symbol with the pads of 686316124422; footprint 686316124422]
Designator prefix K

## 686316124422  [686316124422]
1  1
2  2
3  3
4  4
5  5
6  6
7  7
8  8
9  9
10  10
11  11
12  12
13  13
14  14
15  15
16  16

## Footprint 686316124422 (pad centres in mm)
WR-FPC-1.00mm SMT ZIF Vertical Type A,16 pins
smd 0.42 x 1.5: 1 -6.58,-1.25; 2 -5.58,1.25; 3 -4.58,-1.25; 4 -3.58,1.25; 5 -2.58,-1.25; 6 -1.58,1.25; 7 -0.58,-1.25; 8 0.42,1.25; 9 1.42,-1.25; 10 2.42,1.25; 11 3.42,-1.25; 12 4.42,1.25; 13 5.42,-1.25; 14 6.42,1.25; 15 7.42,-1.25; 16 8.42,1.25
smd 1.8 x 2: Z1 -8.69,0; Z2 10.53,0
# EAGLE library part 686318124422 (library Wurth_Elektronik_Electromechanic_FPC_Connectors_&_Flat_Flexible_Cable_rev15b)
WR-FPC-1.00mm SMT ZIF Vertical Type A,18 pins=>Code : Con_FPC_ZIF_1.00_686318124422 Details see: http://katalog.we-online.de/en/em/686_3xx_124_422 Created 2014-07-09, Karrer Zheng 2014 (C) Würth Elektronik

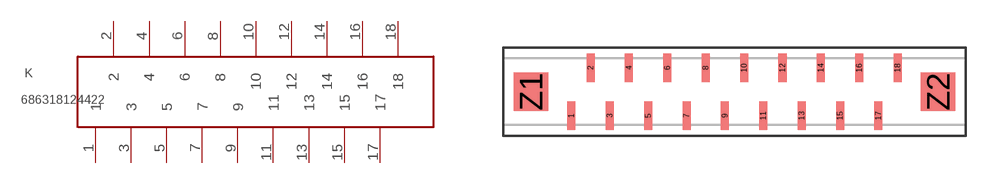
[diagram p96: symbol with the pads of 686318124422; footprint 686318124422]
Designator prefix K

## 686318124422  [686318124422]
1  1
2  2
3  3
4  4
5  5
6  6
7  7
8  8
9  9
10  10
11  11
12  12
13  13
14  14
15  15
16  16
17  17
18  18

## Footprint 686318124422 (pad centres in mm)
WR-FPC-1.00mm SMT ZIF Vertical Type A,18 pins
smd 0.42 x 1.5: 1 -7.85,-1.25; 2 -6.85,1.25; 3 -5.85,-1.25; 4 -4.85,1.25; 5 -3.85,-1.25; 6 -2.85,1.25; 7 -1.85,-1.25; 8 -0.85,1.25; 9 0.15,-1.25; 10 1.15,1.25; 11 2.15,-1.25; 12 3.15,1.25; 13 4.15,-1.25; 14 5.15,1.25; 15 6.15,-1.25; 16 7.15,1.25; 17 8.15,-1.25; 18 9.15,1.25
smd 1.8 x 2: Z1 -9.96,0; Z2 11.26,0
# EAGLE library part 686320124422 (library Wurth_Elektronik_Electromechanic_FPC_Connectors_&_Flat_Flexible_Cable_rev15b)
WR-FPC-1.00mm SMT ZIF Vertical Type A,20 pins=>Code : Con_FPC_ZIF_1.00_686320124422 Details see: http://katalog.we-online.de/en/em/686_3xx_124_422 Created 2014-07-09, Karrer Zheng 2014 (C) Würth Elektronik

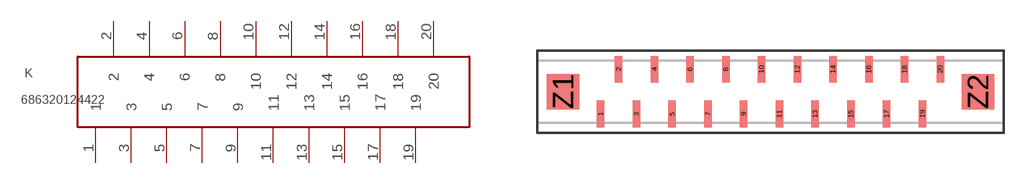
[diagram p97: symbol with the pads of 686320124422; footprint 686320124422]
Designator prefix K

## 686320124422  [686320124422]
1  1
2  2
3  3
4  4
5  5
6  6
7  7
8  8
9  9
10  10
11  11
12  12
13  13
14  14
15  15
16  16
17  17
18  18
19  19
20  20

## Footprint 686320124422 (pad centres in mm)
WR-FPC-1.00mm SMT ZIF Vertical Type A,20 pins
smd 0.42 x 1.5: 1 -9.12,-1.25; 2 -8.12,1.25; 3 -7.12,-1.25; 4 -6.12,1.25; 5 -5.12,-1.25; 6 -4.12,1.25; 7 -3.12,-1.25; 8 -2.12,1.25; 9 -1.12,-1.25; 10 -0.12,1.25; 11 0.88,-1.25; 12 1.88,1.25; 13 2.88,-1.25; 14 3.88,1.25; 15 4.88,-1.25; 16 5.88,1.25; 17 6.88,-1.25; 18 7.88,1.25; 19 8.88,-1.25; 20 9.88,1.25
smd 1.8 x 2: Z1 -11.23,0; Z2 11.99,0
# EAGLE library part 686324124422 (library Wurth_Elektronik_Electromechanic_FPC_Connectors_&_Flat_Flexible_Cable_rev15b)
WR-FPC-1.00mm SMT ZIF Vertical Type A,24 pins=>Code : Con_FPC_ZIF_1.00_686324124422 Details see: http://katalog.we-online.de/en/em/686_3xx_124_422 Created 2014-07-09, Karrer Zheng 2014 (C) Würth Elektronik

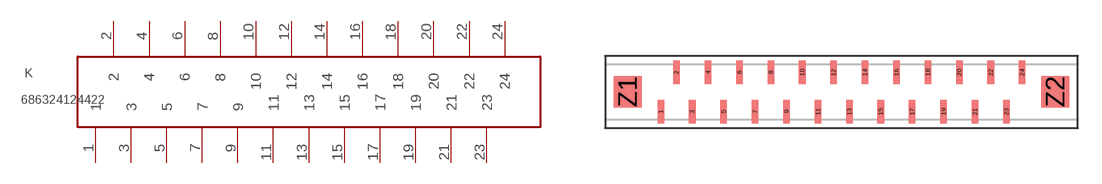
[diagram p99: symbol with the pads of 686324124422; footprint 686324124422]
Designator prefix K

## 686324124422  [686324124422]
1  1
2  2
3  3
4  4
5  5
6  6
7  7
8  8
9  9
10  10
11  11
12  12
13  13
14  14
15  15
16  16
17  17
18  18
19  19
20  20
21  21
22  22
23  23
24  24

## Footprint 686324124422 (pad centres in mm)
WR-FPC-1.00mm SMT ZIF Vertical Type A,24 pins
smd 0.42 x 1.5: 1 -10.39,-1.25; 2 -9.39,1.25; 3 -8.39,-1.25; 4 -7.39,1.25; 5 -6.39,-1.25; 6 -5.39,1.25; 7 -4.39,-1.25; 8 -3.39,1.25; 9 -2.39,-1.25; 10 -1.39,1.25; 11 -0.39,-1.25; 12 0.61,1.25; 13 1.61,-1.25; 14 2.61,1.25; 15 3.61,-1.25; 16 4.61,1.25; 17 5.61,-1.25; 18 6.61,1.25; 19 7.61,-1.25; 20 8.61,1.25; 21 9.61,-1.25; 22 10.61,1.25; 23 11.61,-1.25; 24 12.61,1.25
smd 1.8 x 2: Z1 -12.5,0; Z2 14.72,0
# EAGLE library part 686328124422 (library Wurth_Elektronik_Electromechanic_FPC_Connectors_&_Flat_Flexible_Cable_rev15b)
WR-FPC-1.00mm SMT ZIF Vertical Type A,28 pins=>Code : Con_FPC_ZIF_1.00_686328124422 Details see: http://katalog.we-online.de/en/em/686_3xx_124_422 Created 2014-07-09, Karrer Zheng 2014 (C) Würth Elektronik

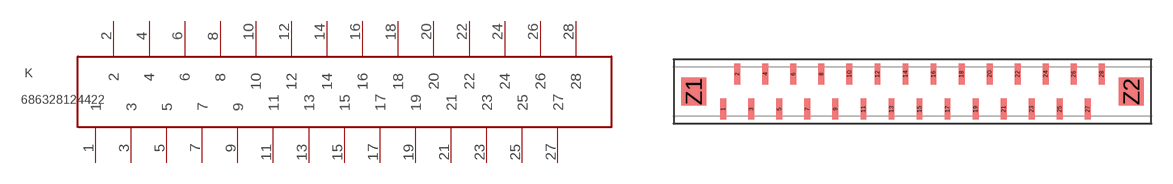
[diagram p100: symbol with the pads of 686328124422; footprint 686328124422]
Designator prefix K

## 686328124422  [686328124422]
1  1
2  2
3  3
4  4
5  5
6  6
7  7
8  8
9  9
10  10
11  11
12  12
13  13
14  14
15  15
16  16
17  17
18  18
19  19
20  20
21  21
22  22
23  23
24  24
25  25
26  26
27  27
28  28

## Footprint 686328124422 (pad centres in mm)
WR-FPC-1.00mm SMT ZIF Vertical Type A,28 pins
smd 0.42 x 1.5: 1 -11.66,-1.25; 2 -10.66,1.25; 3 -9.66,-1.25; 4 -8.66,1.25; 5 -7.66,-1.25; 6 -6.66,1.25; 7 -5.66,-1.25; 8 -4.66,1.25; 9 -3.66,-1.25; 10 -2.66,1.25; 11 -1.66,-1.25; 12 -0.66,1.25; 13 0.34,-1.25; 14 1.34,1.25; 15 2.34,-1.25; 16 3.34,1.25; 17 4.34,-1.25; 18 5.34,1.25; 19 6.34,-1.25; 20 7.34,1.25; 21 8.34,-1.25; 22 9.34,1.25; 23 10.34,-1.25; 24 11.34,1.25; 25 12.34,-1.25; 26 13.34,1.25; 27 14.34,-1.25; 28 15.34,1.25
smd 1.8 x 2: Z1 -13.77,0; Z2 17.45,0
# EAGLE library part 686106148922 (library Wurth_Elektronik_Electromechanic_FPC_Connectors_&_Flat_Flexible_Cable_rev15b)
WR-FPC 1mm SMT Horiz. Bot. Contact Hinge type WR-FPC 1mm 06 pins Hinge type SMT Horizontal Bottom Contact ;=>Code : Con_FPC_ZIF_1.00_6861xx148922_686106148922 Details see: http://katalog.we-online.de/em/datasheet/6861xx148922.pdf Created 2014-10-08, Karrer Zheng 2014 (C) Wurth Elektronik

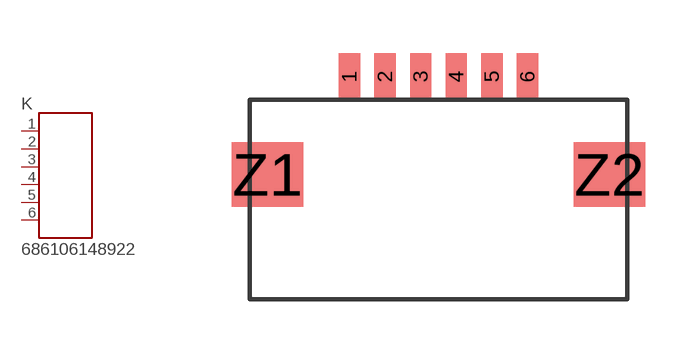
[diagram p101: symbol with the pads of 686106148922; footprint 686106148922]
Designator prefix K

## 686106148922  [686106148922]
1  1  pas
2  2  pas
3  3  pas
4  4  pas
5  5  pas
6  6  pas

## Footprint 686106148922 (pad centres in mm)
WR-FPC 1mm SMT Horiz. Bot. Contact Hinge type WR-FPC 1mm 06pins Hinge type SMT Horizontal Bottom Contact
smd 0.6 x 1.3: 1 -2.5,0; 2 -1.5,0; 3 -0.5,0; 4 0.5,0; 5 1.5,0; 6 2.5,0
smd 2 x 1.8: Z1 -4.8,-2.75; Z2 4.8,-2.75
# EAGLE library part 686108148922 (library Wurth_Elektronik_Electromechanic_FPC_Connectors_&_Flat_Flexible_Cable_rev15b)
WR-FPC 1mm SMT Horiz. Bot. Contact Hinge type WR-FPC 1mm 08 pins Hinge type SMT Horizontal Bottom Contact ;=>Code : Con_FPC_ZIF_1.00_6861xx148922_686108148922 Details see: http://katalog.we-online.de/em/datasheet/6861xx148922.pdf Created 2014-10-08, Karrer Zheng 2014 (C) Wurth Elektronik

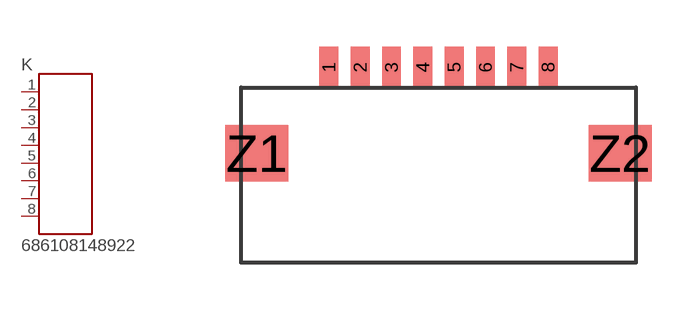
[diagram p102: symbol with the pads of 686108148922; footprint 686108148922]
Designator prefix K

## 686108148922  [686108148922]
1  1  pas
2  2  pas
3  3  pas
4  4  pas
5  5  pas
6  6  pas
7  7  pas
8  8  pas

## Footprint 686108148922 (pad centres in mm)
WR-FPC 1mm SMT Horiz. Bot. Contact Hinge type WR-FPC 1mm 08pins Hinge type SMT Horizontal Bottom Contact
smd 0.6 x 1.3: 1 -3.5,0; 2 -2.5,0; 3 -1.5,0; 4 -0.5,0; 5 0.5,0; 6 1.5,0; 7 2.5,0; 8 3.5,0
smd 2 x 1.8: Z1 -5.8,-2.75; Z2 5.8,-2.75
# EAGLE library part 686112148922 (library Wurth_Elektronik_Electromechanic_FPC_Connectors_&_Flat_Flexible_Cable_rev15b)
WR-FPC 1mm SMT Horiz. Bot. Contact Hinge type WR-FPC 1mm 12 pins Hinge type SMT Horizontal Bottom Contact ;=>Code : Con_FPC_ZIF_1.00_6861xx148922_686112148922 Details see: http://katalog.we-online.de/em/datasheet/6861xx148922.pdf Created 2014-10-08, Karrer Zheng 2014 (C) Wurth Elektronik

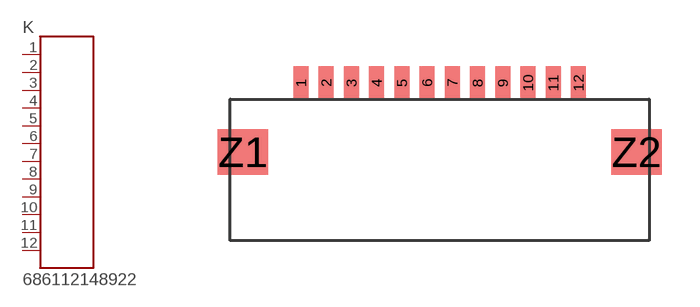
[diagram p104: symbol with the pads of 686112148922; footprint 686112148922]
Designator prefix K

## 686112148922  [686112148922]
1  1  pas
2  2  pas
3  3  pas
4  4  pas
5  5  pas
6  6  pas
7  7  pas
8  8  pas
9  9  pas
10  10  pas
11  11  pas
12  12  pas

## Footprint 686112148922 (pad centres in mm)
WR-FPC 1mm SMT Horiz. Bot. Contact Hinge type WR-FPC 1mm 12pins Hinge type SMT Horizontal Bottom Contact
smd 0.6 x 1.3: 1 -5.5,0; 2 -4.5,0; 3 -3.5,0; 4 -2.5,0; 5 -1.5,0; 6 -0.5,0; 7 0.5,0; 8 1.5,0; 9 2.5,0; 10 3.5,0; 11 4.5,0; 12 5.5,0
smd 2 x 1.8: Z1 -7.8,-2.75; Z2 7.8,-2.75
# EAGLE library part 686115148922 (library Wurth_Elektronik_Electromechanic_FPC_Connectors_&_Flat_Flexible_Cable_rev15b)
WR-FPC 1mm SMT Horiz. Bot. Contact Hinge type WR-FPC 1mm 15 pins Hinge type SMT Horizontal Bottom Contact ;=>Code : Con_FPC_ZIF_1.00_6861xx148922_686115148922 Details see: http://katalog.we-online.de/em/datasheet/6861xx148922.pdf Created 2014-10-08, Karrer Zheng 2014 (C) Wurth Elektronik

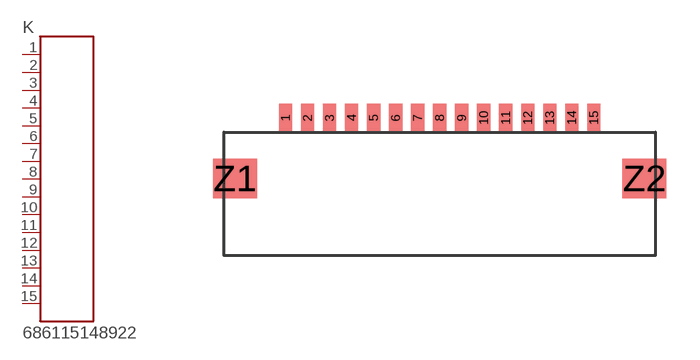
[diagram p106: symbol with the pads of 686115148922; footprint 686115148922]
Designator prefix K

## 686115148922  [686115148922]
1  1  pas
2  2  pas
3  3  pas
4  4  pas
5  5  pas
6  6  pas
7  7  pas
8  8  pas
9  9  pas
10  10  pas
11  11  pas
12  12  pas
13  13  pas
14  14  pas
15  15  pas

## Footprint 686115148922 (pad centres in mm)
WR-FPC 1mm SMT Horiz. Bot. Contact Hinge type WR-FPC 1mm 15pins Hinge type SMT Horizontal Bottom Contact
smd 0.6 x 1.3: 1 -7,0; 2 -6,0; 3 -5,0; 4 -4,0; 5 -3,0; 6 -2,0; 7 -1,0; 8 0,0; 9 1,0; 10 2,0; 11 3,0; 12 4,0; 13 5,0; 14 6,0; 15 7,0
smd 2 x 1.8: Z1 -9.3,-2.75; Z2 9.3,-2.75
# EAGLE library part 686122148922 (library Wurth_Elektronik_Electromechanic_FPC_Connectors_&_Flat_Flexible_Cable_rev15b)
WR-FPC 1mm SMT Horiz. Bot. Contact Hinge type WR-FPC 1mm 22 pins Hinge type SMT Horizontal Bottom Contact ;=>Code : Con_FPC_ZIF_1.00_6861xx148922_686122148922 Details see: http://katalog.we-online.de/em/datasheet/6861xx148922.pdf Created 2014-10-08, Karrer Zheng 2014 (C) Wurth Elektronik

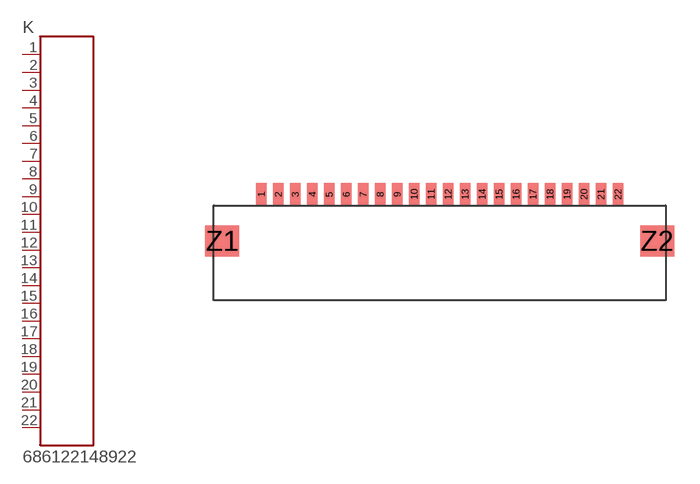
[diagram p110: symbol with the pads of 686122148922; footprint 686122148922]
Designator prefix K

## 686122148922  [686122148922]
1  1  pas
2  2  pas
3  3  pas
4  4  pas
5  5  pas
6  6  pas
7  7  pas
8  8  pas
9  9  pas
10  10  pas
11  11  pas
12  12  pas
13  13  pas
14  14  pas
15  15  pas
16  16  pas
17  17  pas
18  18  pas
19  19  pas
20  20  pas
21  21  pas
22  22  pas

## Footprint 686122148922 (pad centres in mm)
WR-FPC 1mm SMT Horiz. Bot. Contact Hinge type WR-FPC 1mm 22pins Hinge type SMT Horizontal Bottom Contact
smd 0.6 x 1.3: 1 -10.5,0; 2 -9.5,0; 3 -8.5,0; 4 -7.5,0; 5 -6.5,0; 6 -5.5,0; 7 -4.5,0; 8 -3.5,0; 9 -2.5,0; 10 -1.5,0; 11 -0.5,0; 12 0.5,0; 13 1.5,0; 14 2.5,0; 15 3.5,0; 16 4.5,0; 17 5.5,0; 18 6.5,0; 19 7.5,0; 20 8.5,0; 21 9.5,0; 22 10.5,0
smd 2 x 1.8: Z1 -12.8,-2.75; Z2 12.8,-2.75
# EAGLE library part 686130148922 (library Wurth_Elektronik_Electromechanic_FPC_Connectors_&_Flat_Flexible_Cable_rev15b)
WR-FPC 1mm SMT Horiz. Bot. Contact Hinge type WR-FPC 1mm 30 pins Hinge type SMT Horizontal Bottom Contact ;=>Code : Con_FPC_ZIF_1.00_6861xx148922_686130148922 Details see: http://katalog.we-online.de/em/datasheet/6861xx148922.pdf Created 2014-10-08, Karrer Zheng 2014 (C) Wurth Elektronik

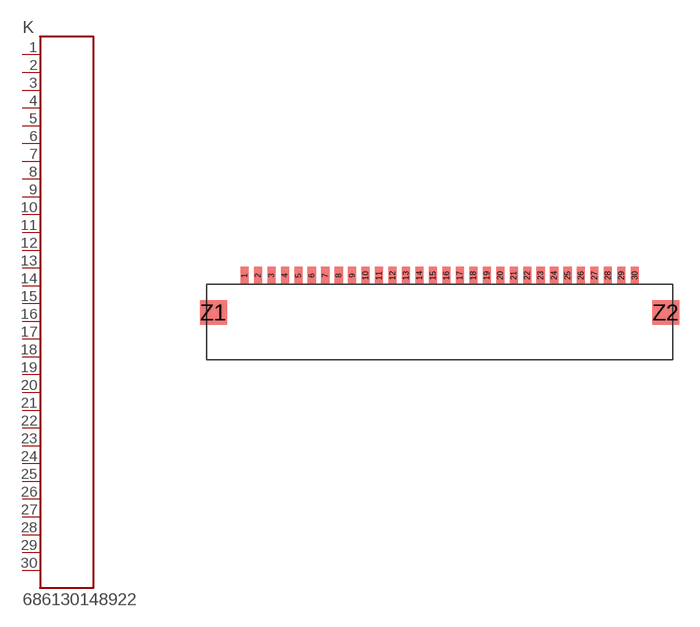
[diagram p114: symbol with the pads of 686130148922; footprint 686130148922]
Designator prefix K

## 686130148922  [686130148922]
1  1  pas
2  2  pas
3  3  pas
4  4  pas
5  5  pas
6  6  pas
7  7  pas
8  8  pas
9  9  pas
10  10  pas
11  11  pas
12  12  pas
13  13  pas
14  14  pas
15  15  pas
16  16  pas
17  17  pas
18  18  pas
19  19  pas
20  20  pas
21  21  pas
22  22  pas
23  23  pas
24  24  pas
25  25  pas
26  26  pas
27  27  pas
28  28  pas
29  29  pas
30  30  pas

## Footprint 686130148922 (pad centres in mm)
WR-FPC 1mm SMT Horiz. Bot. Contact Hinge type WR-FPC 1mm 30pins Hinge type SMT Horizontal Bottom Contact
smd 0.6 x 1.3: 1 -14.5,0; 2 -13.5,0; 3 -12.5,0; 4 -11.5,0; 5 -10.5,0; 6 -9.5,0; 7 -8.5,0; 8 -7.5,0; 9 -6.5,0; 10 -5.5,0; 11 -4.5,0; 12 -3.5,0; 13 -2.5,0; 14 -1.5,0; 15 -0.5,0; 16 0.5,0; 17 1.5,0; 18 2.5,0; 19 3.5,0; 20 4.5,0; 21 5.5,0; 22 6.5,0; 23 7.5,0; 24 8.5,0; 25 9.5,0; 26 10.5,0; 27 11.5,0; 28 12.5,0; 29 13.5,0; 30 14.5,0
smd 2 x 1.8: Z1 -16.8,-2.75; Z2 16.8,-2.75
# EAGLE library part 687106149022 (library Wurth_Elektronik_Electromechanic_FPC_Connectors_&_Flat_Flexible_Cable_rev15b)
WR-FPC 0.50mm SMT Horiz. Bot. Contact Hinge type WR-FPC 0.50mm 6 pins Hinge type SMT Horizontal Bottom Contact ;=>Code : Con_FPC_ZIF_0.50_6871xx149022_687106149022 Details see: http://katalog.we-online.de/em/datasheet/6871xx149022.pdf Created 2014-10-08, Karrer Zheng 2014 (C) Wurth Elektronik

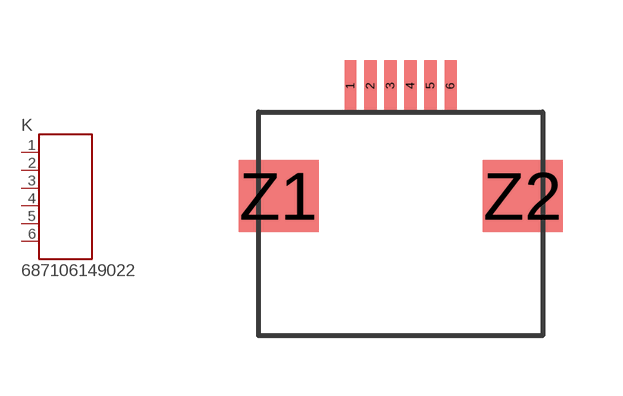
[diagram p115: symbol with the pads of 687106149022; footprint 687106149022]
Designator prefix K

## 687106149022  [687106149022]
1  1  pas
2  2  pas
3  3  pas
4  4  pas
5  5  pas
6  6  pas

## Footprint 687106149022 (pad centres in mm)
WR-FPC 0.50mm SMT Horiz. Bot. Contact Hinge type WR-FPC 0.50mm 6pins Hinge type SMT Horizontal Bottom Contact
smd 0.3 x 1.3: 1 -1.25,0; 2 -0.75,0; 3 -0.25,0; 4 0.25,0; 5 0.75,0; 6 1.25,0
smd 2 x 1.8: Z1 -3.05,-2.75; Z2 3.05,-2.75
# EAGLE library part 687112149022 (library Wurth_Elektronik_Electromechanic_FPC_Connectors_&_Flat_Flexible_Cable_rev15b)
WR-FPC 0.50mm SMT Horiz. Bot. Contact Hinge type WR-FPC 0.50mm 12 pins Hinge type SMT Horizontal Bottom Contact ;=>Code : Con_FPC_ZIF_0.50_6871xx149022_687112149022 Details see: http://katalog.we-online.de/em/datasheet/6871xx149022.pdf Created 2014-10-08, Karrer Zheng 2014 (C) Wurth Elektronik

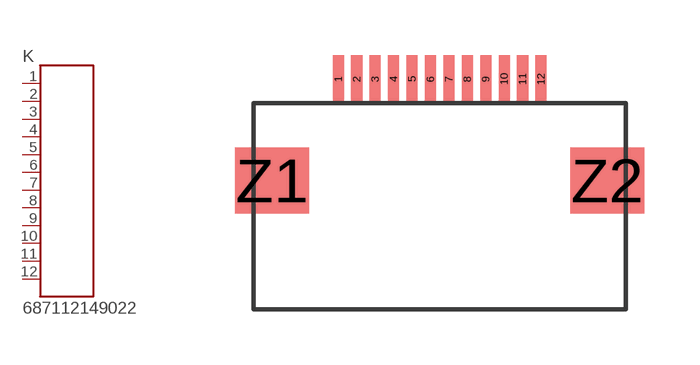
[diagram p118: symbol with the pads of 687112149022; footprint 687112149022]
Designator prefix K

## 687112149022  [687112149022]
1  1  pas
2  2  pas
3  3  pas
4  4  pas
5  5  pas
6  6  pas
7  7  pas
8  8  pas
9  9  pas
10  10  pas
11  11  pas
12  12  pas

## Footprint 687112149022 (pad centres in mm)
WR-FPC 0.50mm SMT Horiz. Bot. Contact Hinge type WR-FPC 0.50mm 12pins Hinge type SMT Horizontal Bottom Contact
smd 0.3 x 1.3: 1 -2.75,0; 2 -2.25,0; 3 -1.75,0; 4 -1.25,0; 5 -0.75,0; 6 -0.25,0; 7 0.25,0; 8 0.75,0; 9 1.25,0; 10 1.75,0; 11 2.25,0; 12 2.75,0
smd 2 x 1.8: Z1 -4.55,-2.75; Z2 4.55,-2.75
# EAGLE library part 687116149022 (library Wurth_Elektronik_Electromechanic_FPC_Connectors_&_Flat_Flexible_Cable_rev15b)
WR-FPC 0.50mm SMT Horiz. Bot. Contact Hinge type WR-FPC 0.50mm 16 pins Hinge type SMT Horizontal Bottom Contact ;=>Code : Con_FPC_ZIF_0.50_6871xx149022_687116149022 Details see: http://katalog.we-online.de/em/datasheet/6871xx149022.pdf Created 2014-10-08, Karrer Zheng 2014 (C) Wurth Elektronik

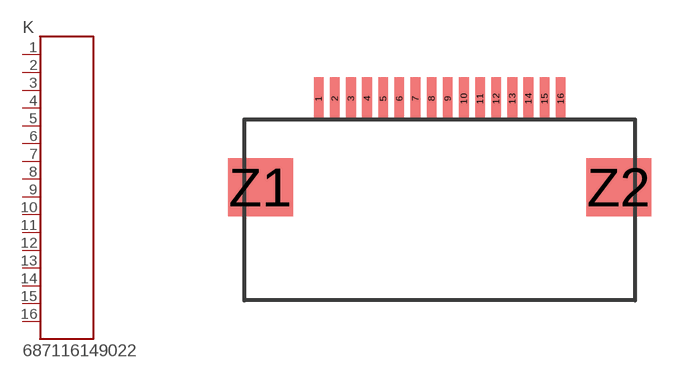
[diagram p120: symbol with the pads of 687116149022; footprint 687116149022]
Designator prefix K

## 687116149022  [687116149022]
1  1  pas
2  2  pas
3  3  pas
4  4  pas
5  5  pas
6  6  pas
7  7  pas
8  8  pas
9  9  pas
10  10  pas
11  11  pas
12  12  pas
13  13  pas
14  14  pas
15  15  pas
16  16  pas

## Footprint 687116149022 (pad centres in mm)
WR-FPC 0.50mm SMT Horiz. Bot. Contact Hinge type WR-FPC 0.50mm 16pins Hinge type SMT Horizontal Bottom Contact
smd 0.3 x 1.3: 1 -3.75,0; 2 -3.25,0; 3 -2.75,0; 4 -2.25,0; 5 -1.75,0; 6 -1.25,0; 7 -0.75,0; 8 -0.25,0; 9 0.25,0; 10 0.75,0; 11 1.25,0; 12 1.75,0; 13 2.25,0; 14 2.75,0; 15 3.25,0; 16 3.75,0
smd 2 x 1.8: Z1 -5.55,-2.75; Z2 5.55,-2.75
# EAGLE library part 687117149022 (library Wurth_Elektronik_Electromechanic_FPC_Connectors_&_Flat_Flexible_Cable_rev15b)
WR-FPC 0.50mm SMT Horiz. Bot. Contact Hinge type WR-FPC 0.50mm 17 pins Hinge type SMT Horizontal Bottom Contact ;=>Code : Con_FPC_ZIF_0.50_6871xx149022_687117149022 Details see: http://katalog.we-online.de/em/datasheet/6871xx149022.pdf Created 2014-10-08, Karrer Zheng 2014 (C) Wurth Elektronik

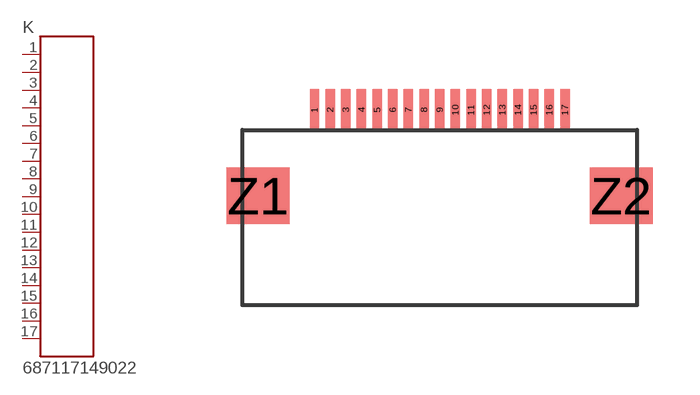
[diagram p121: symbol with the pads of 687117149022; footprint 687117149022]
Designator prefix K

## 687117149022  [687117149022]
1  1  pas
2  2  pas
3  3  pas
4  4  pas
5  5  pas
6  6  pas
7  7  pas
8  8  pas
9  9  pas
10  10  pas
11  11  pas
12  12  pas
13  13  pas
14  14  pas
15  15  pas
16  16  pas
17  17  pas

## Footprint 687117149022 (pad centres in mm)
WR-FPC 0.50mm SMT Horiz. Bot. Contact Hinge type WR-FPC 0.50mm 17pins Hinge type SMT Horizontal Bottom Contact
smd 0.3 x 1.3: 1 -4,0; 2 -3.5,0; 3 -3,0; 4 -2.5,0; 5 -2,0; 6 -1.5,0; 7 -1,0; 8 -0.5,0; 9 0,0; 10 0.5,0; 11 1,0; 12 1.5,0; 13 2,0; 14 2.5,0; 15 3,0; 16 3.5,0; 17 4,0
smd 2 x 1.8: Z1 -5.8,-2.75; Z2 5.8,-2.75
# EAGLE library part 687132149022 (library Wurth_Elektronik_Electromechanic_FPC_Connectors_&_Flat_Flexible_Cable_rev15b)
WR-FPC 0.50mm SMT Horiz. Bot. Contact Hinge type WR-FPC 0.50mm 32 pins Hinge type SMT Horizontal Bottom Contact ;=>Code : Con_FPC_ZIF_0.50_6871xx149022_687132149022 Details see: http://katalog.we-online.de/em/datasheet/6871xx149022.pdf Created 2014-10-08, Karrer Zheng 2014 (C) Wurth Elektronik

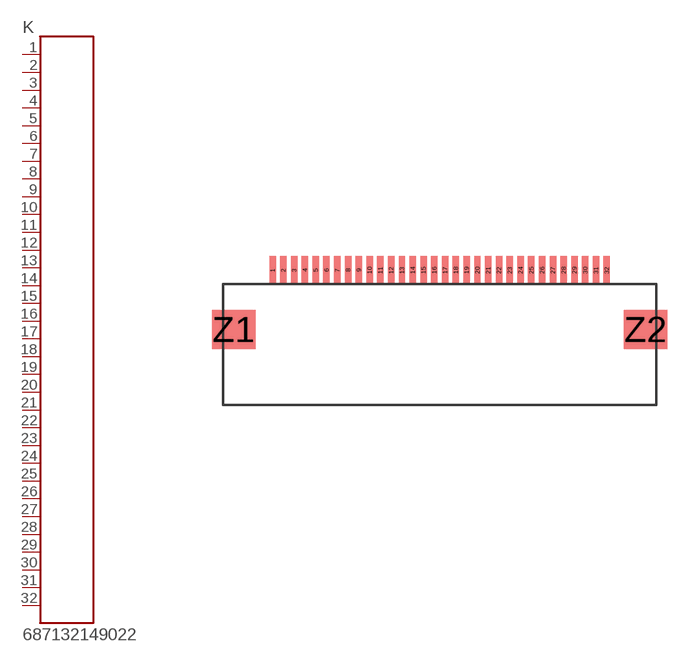
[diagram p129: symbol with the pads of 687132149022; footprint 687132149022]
Designator prefix K

## 687132149022  [687132149022]
1  1  pas
2  2  pas
3  3  pas
4  4  pas
5  5  pas
6  6  pas
7  7  pas
8  8  pas
9  9  pas
10  10  pas
11  11  pas
12  12  pas
13  13  pas
14  14  pas
15  15  pas
16  16  pas
17  17  pas
18  18  pas
19  19  pas
20  20  pas
21  21  pas
22  22  pas
23  23  pas
24  24  pas
25  25  pas
26  26  pas
27  27  pas
28  28  pas
29  29  pas
30  30  pas
31  31  pas
32  32  pas

## Footprint 687132149022 (pad centres in mm)
WR-FPC 0.50mm SMT Horiz. Bot. Contact Hinge type WR-FPC 0.50mm 32pins Hinge type SMT Horizontal Bottom Contact
smd 0.3 x 1.3: 1 -7.75,0; 2 -7.25,0; 3 -6.75,0; 4 -6.25,0; 5 -5.75,0; 6 -5.25,0; 7 -4.75,0; 8 -4.25,0; 9 -3.75,0; 10 -3.25,0; 11 -2.75,0; 12 -2.25,0; 13 -1.75,0; 14 -1.25,0; 15 -0.75,0; 16 -0.25,0; 17 0.25,0; 18 0.75,0; 19 1.25,0; 20 1.75,0; 21 2.25,0; 22 2.75,0; 23 3.25,0; 24 3.75,0; 25 4.25,0; 26 4.75,0; 27 5.25,0; 28 5.75,0; 29 6.25,0; 30 6.75,0; 31 7.25,0; 32 7.75,0
smd 2 x 1.8: Z1 -9.55,-2.75; Z2 9.55,-2.75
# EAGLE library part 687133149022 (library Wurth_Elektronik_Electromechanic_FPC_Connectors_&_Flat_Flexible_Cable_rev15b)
WR-FPC 0.50mm SMT Horiz. Bot. Contact Hinge type WR-FPC 0.50mm 33 pins Hinge type SMT Horizontal Bottom Contact ;=>Code : Con_FPC_ZIF_0.50_6871xx149022_687133149022 Details see: http://katalog.we-online.de/em/datasheet/6871xx149022.pdf Created 2014-10-08, Karrer Zheng 2014 (C) Wurth Elektronik

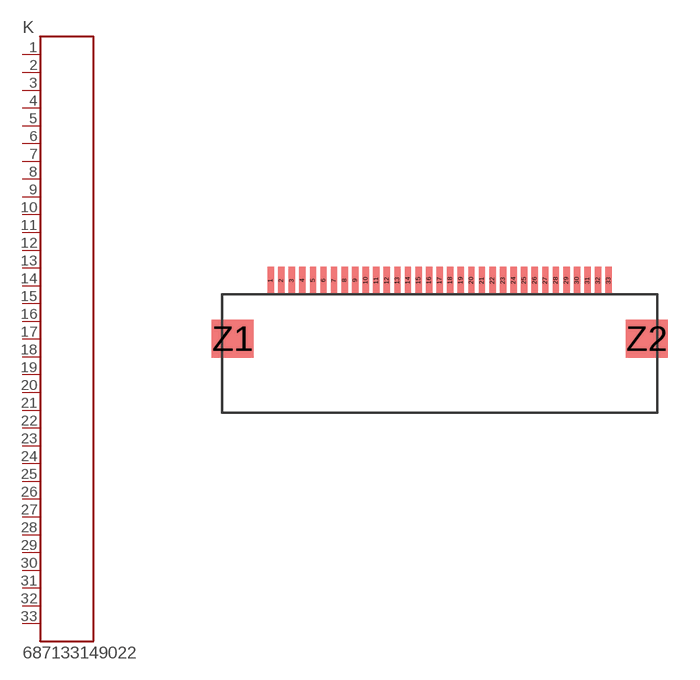
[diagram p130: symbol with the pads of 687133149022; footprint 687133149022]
Designator prefix K

## 687133149022  [687133149022]
1  1  pas
2  2  pas
3  3  pas
4  4  pas
5  5  pas
6  6  pas
7  7  pas
8  8  pas
9  9  pas
10  10  pas
11  11  pas
12  12  pas
13  13  pas
14  14  pas
15  15  pas
16  16  pas
17  17  pas
18  18  pas
19  19  pas
20  20  pas
21  21  pas
22  22  pas
23  23  pas
24  24  pas
25  25  pas
26  26  pas
27  27  pas
28  28  pas
29  29  pas
30  30  pas
31  31  pas
32  32  pas
33  33  pas

## Footprint 687133149022 (pad centres in mm)
WR-FPC 0.50mm SMT Horiz. Bot. Contact Hinge type WR-FPC 0.50mm 33pins Hinge type SMT Horizontal Bottom Contact
smd 0.3 x 1.3: 1 -8,0; 2 -7.5,0; 3 -7,0; 4 -6.5,0; 5 -6,0; 6 -5.5,0; 7 -5,0; 8 -4.5,0; 9 -4,0; 10 -3.5,0; 11 -3,0; 12 -2.5,0; 13 -2,0; 14 -1.5,0; 15 -1,0; 16 -0.5,0; 17 0,0; 18 0.5,0; 19 1,0; 20 1.5,0; 21 2,0; 22 2.5,0; 23 3,0; 24 3.5,0; 25 4,0; 26 4.5,0; 27 5,0; 28 5.5,0; 29 6,0; 30 6.5,0; 31 7,0; 32 7.5,0; 33 8,0
smd 2 x 1.8: Z1 -9.8,-2.75; Z2 9.8,-2.75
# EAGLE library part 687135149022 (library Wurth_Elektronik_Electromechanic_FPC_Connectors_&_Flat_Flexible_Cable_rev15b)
WR-FPC 0.50mm SMT Horiz. Bot. Contact Hinge type WR-FPC 0.50mm 35 pins Hinge type SMT Horizontal Bottom Contact ;=>Code : Con_FPC_ZIF_0.50_6871xx149022_687135149022 Details see: http://katalog.we-online.de/em/datasheet/6871xx149022.pdf Created 2014-10-08, Karrer Zheng 2014 (C) Wurth Elektronik

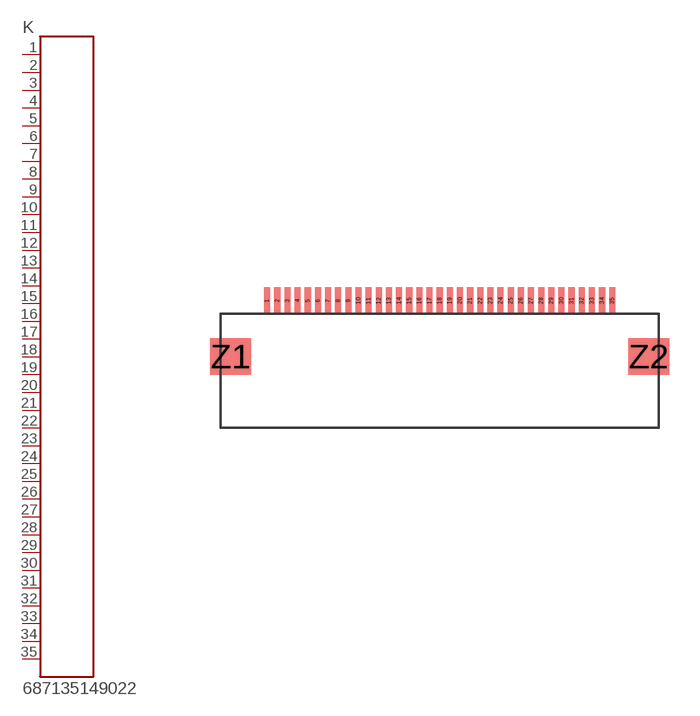
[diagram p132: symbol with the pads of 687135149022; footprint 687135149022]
Designator prefix K

## 687135149022  [687135149022]
1  1  pas
2  2  pas
3  3  pas
4  4  pas
5  5  pas
6  6  pas
7  7  pas
8  8  pas
9  9  pas
10  10  pas
11  11  pas
12  12  pas
13  13  pas
14  14  pas
15  15  pas
16  16  pas
17  17  pas
18  18  pas
19  19  pas
20  20  pas
21  21  pas
22  22  pas
23  23  pas
24  24  pas
25  25  pas
26  26  pas
27  27  pas
28  28  pas
29  29  pas
30  30  pas
31  31  pas
32  32  pas
33  33  pas
34  34  pas
35  35  pas

## Footprint 687135149022 (pad centres in mm)
WR-FPC 0.50mm SMT Horiz. Bot. Contact Hinge type WR-FPC 0.50mm 35pins Hinge type SMT Horizontal Bottom Contact
smd 0.3 x 1.3: 1 -8.5,0; 2 -8,0; 3 -7.5,0; 4 -7,0; 5 -6.5,0; 6 -6,0; 7 -5.5,0; 8 -5,0; 9 -4.5,0; 10 -4,0; 11 -3.5,0; 12 -3,0; 13 -2.5,0; 14 -2,0; 15 -1.5,0; 16 -1,0; 17 -0.5,0; 18 0,0; 19 0.5,0; 20 1,0; 21 1.5,0; 22 2,0; 23 2.5,0; 24 3,0; 25 3.5,0; 26 4,0; 27 4.5,0; 28 5,0; 29 5.5,0; 30 6,0; 31 6.5,0; 32 7,0; 33 7.5,0; 34 8,0; 35 8.5,0
smd 2 x 1.8: Z1 -10.3,-2.75; Z2 10.3,-2.75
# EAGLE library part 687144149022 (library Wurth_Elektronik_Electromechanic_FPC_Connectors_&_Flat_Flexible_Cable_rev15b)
WR-FPC 0.50mm SMT Horiz. Bot. Contact Hinge type WR-FPC 0.50mm 44 pins Hinge type SMT Horizontal Bottom Contact ;=>Code : Con_FPC_ZIF_0.50_6871xx149022_687144149022 Details see: http://katalog.we-online.de/em/datasheet/6871xx149022.pdf Created 2014-10-08, Karrer Zheng 2014 (C) Wurth Elektronik

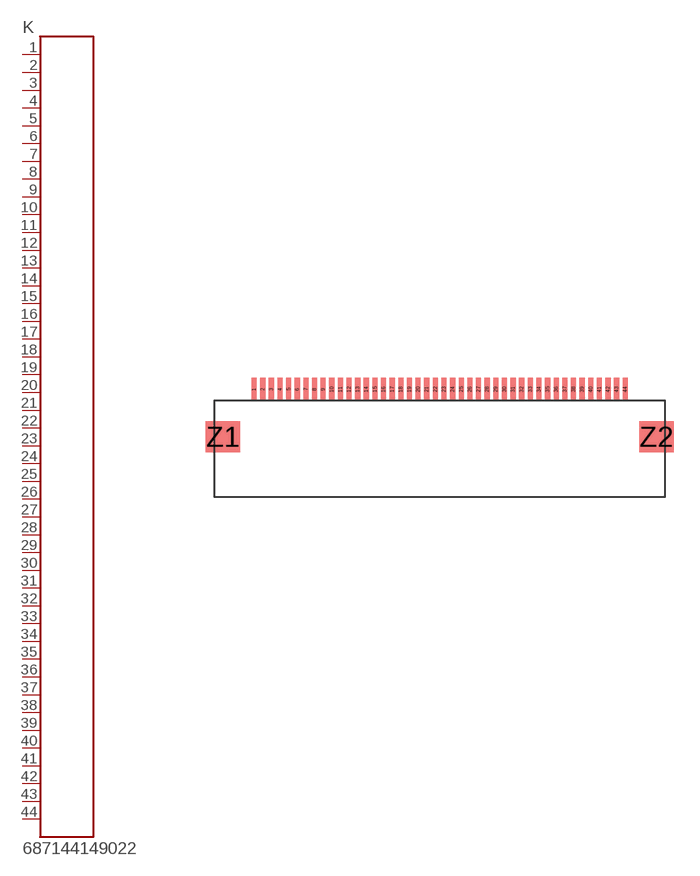
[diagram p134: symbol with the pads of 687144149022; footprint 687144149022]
Designator prefix K

## 687144149022  [687144149022]
1  1  pas
2  2  pas
3  3  pas
4  4  pas
5  5  pas
6  6  pas
7  7  pas
8  8  pas
9  9  pas
10  10  pas
11  11  pas
12  12  pas
13  13  pas
14  14  pas
15  15  pas
16  16  pas
17  17  pas
18  18  pas
19  19  pas
20  20  pas
21  21  pas
22  22  pas
23  23  pas
24  24  pas
25  25  pas
26  26  pas
27  27  pas
28  28  pas
29  29  pas
30  30  pas
31  31  pas
32  32  pas
33  33  pas
34  34  pas
35  35  pas
36  36  pas
37  37  pas
38  38  pas
39  39  pas
40  40  pas
41  41  pas
42  42  pas
43  43  pas
44  44  pas

## Footprint 687144149022 (pad centres in mm)
WR-FPC 0.50mm SMT Horiz. Bot. Contact Hinge type WR-FPC 0.50mm 44pins Hinge type SMT Horizontal Bottom Contact
smd 0.3 x 1.3: 1 -10.75,0; 2 -10.25,0; 3 -9.75,0; 4 -9.25,0; 5 -8.75,0; 6 -8.25,0; 7 -7.75,0; 8 -7.25,0; 9 -6.75,0; 10 -6.25,0; 11 -5.75,0; 12 -5.25,0; 13 -4.75,0; 14 -4.25,0; 15 -3.75,0; 16 -3.25,0; 17 -2.75,0; 18 -2.25,0; 19 -1.75,0; 20 -1.25,0; 21 -0.75,0; 22 -0.25,0; 23 0.25,0; 24 0.75,0; 25 1.25,0; 26 1.75,0; 27 2.25,0; 28 2.75,0; 29 3.25,0; 30 3.75,0; 31 4.25,0; 32 4.75,0; 33 5.25,0; 34 5.75,0; 35 6.25,0; 36 6.75,0; 37 7.25,0; 38 7.75,0; 39 8.25,0; 40 8.75,0; 41 9.25,0; 42 9.75,0; 43 10.25,0; 44 10.75,0
smd 2 x 1.8: Z1 -12.55,-2.75; Z2 12.55,-2.75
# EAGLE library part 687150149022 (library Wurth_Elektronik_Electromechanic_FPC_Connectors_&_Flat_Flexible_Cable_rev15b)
WR-FPC 0.50mm SMT Horiz. Bot. Contact Hinge type WR-FPC 0.50mm 50 pins Hinge type SMT Horizontal Bottom Contact ;=>Code : Con_FPC_ZIF_0.50_6871xx149022_687150149022 Details see: http://katalog.we-online.de/em/datasheet/6871xx149022.pdf Created 2014-10-08, Karrer Zheng 2014 (C) Wurth Elektronik

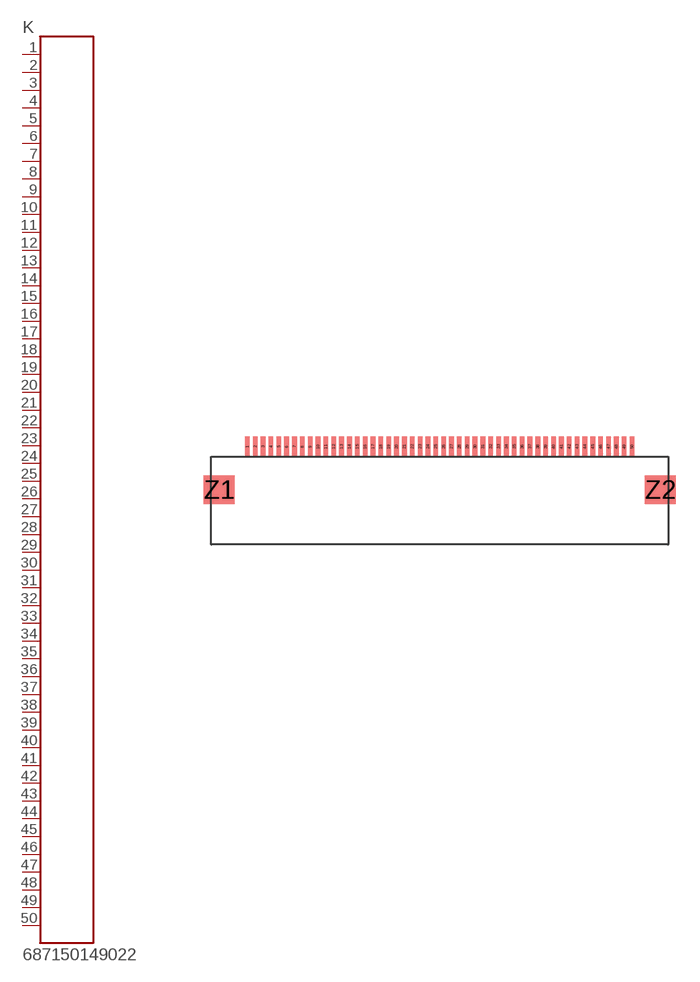
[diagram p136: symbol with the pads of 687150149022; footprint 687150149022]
Designator prefix K

## 687150149022  [687150149022]
1  1  pas
2  2  pas
3  3  pas
4  4  pas
5  5  pas
6  6  pas
7  7  pas
8  8  pas
9  9  pas
10  10  pas
11  11  pas
12  12  pas
13  13  pas
14  14  pas
15  15  pas
16  16  pas
17  17  pas
18  18  pas
19  19  pas
20  20  pas
21  21  pas
22  22  pas
23  23  pas
24  24  pas
25  25  pas
26  26  pas
27  27  pas
28  28  pas
29  29  pas
30  30  pas
31  31  pas
32  32  pas
33  33  pas
34  34  pas
35  35  pas
36  36  pas
37  37  pas
38  38  pas
39  39  pas
40  40  pas
41  41  pas
42  42  pas
43  43  pas
44  44  pas
45  45  pas
46  46  pas
47  47  pas
48  48  pas
49  49  pas
50  50  pas

## Footprint 687150149022 (pad centres in mm)
WR-FPC 0.50mm SMT Horiz. Bot. Contact Hinge type WR-FPC 0.50mm 50pins Hinge type SMT Horizontal Bottom Contact
smd 0.3 x 1.3: 1 -12.25,0; 2 -11.75,0; 3 -11.25,0; 4 -10.75,0; 5 -10.25,0; 6 -9.75,0; 7 -9.25,0; 8 -8.75,0; 9 -8.25,0; 10 -7.75,0; 11 -7.25,0; 12 -6.75,0; 13 -6.25,0; 14 -5.75,0; 15 -5.25,0; 16 -4.75,0; 17 -4.25,0; 18 -3.75,0; 19 -3.25,0; 20 -2.75,0; 21 -2.25,0; 22 -1.75,0; 23 -1.25,0; 24 -0.75,0; 25 -0.25,0; 26 0.25,0; 27 0.75,0; 28 1.25,0; 29 1.75,0; 30 2.25,0; 31 2.75,0; 32 3.25,0; 33 3.75,0; 34 4.25,0; 35 4.75,0; 36 5.25,0; 37 5.75,0; 38 6.25,0; 39 6.75,0; 40 7.25,0; 41 7.75,0; 42 8.25,0; 43 8.75,0; 44 9.25,0; 45 9.75,0; 46 10.25,0; 47 10.75,0; 48 11.25,0; 49 11.75,0; 50 12.25,0
smd 2 x 1.8: Z1 -14.05,-2.75; Z2 14.05,-2.75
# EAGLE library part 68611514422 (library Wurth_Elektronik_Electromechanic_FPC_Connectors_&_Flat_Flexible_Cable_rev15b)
WR-FPC 1.00mm SMT ZIF Horizontal Bottom Contact - 15 Pins;=>Code : Con_FPC_ZIF_1.00_6861xx14422_68611514422 Details see: http://katalog.we-online.de/em/datasheet/6861xx14422.pdf Created 11/27/2014, Karrer Zheng 2014 (C) Wurth Elektronik

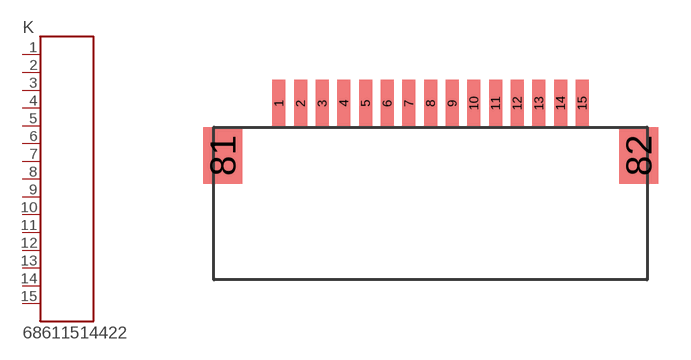
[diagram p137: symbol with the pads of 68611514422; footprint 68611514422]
Designator prefix K

## 68611514422  [68611514422]
1  1  pas
2  2  pas
3  3  pas
4  4  pas
5  5  pas
6  6  pas
7  7  pas
8  8  pas
9  9  pas
10  10  pas
11  11  pas
12  12  pas
13  13  pas
14  14  pas
15  15  pas

## Footprint 68611514422 (pad centres in mm)
WR-FPC 1.00mm SMT ZIF Horizontal Bottom Contact 15 pins;
smd 0.6 x 2.2: 1 -7,0; 2 -6,0; 3 -5,0; 4 -4,0; 5 -3,0; 6 -2,0; 7 -1,0; 8 0,0; 9 1,0; 10 2,0; 11 3,0; 12 4,0; 13 5,0; 14 6,0; 15 7,0
smd 1.8 x 2.6: 81 -9.6,-2.4; 82 9.6,-2.4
